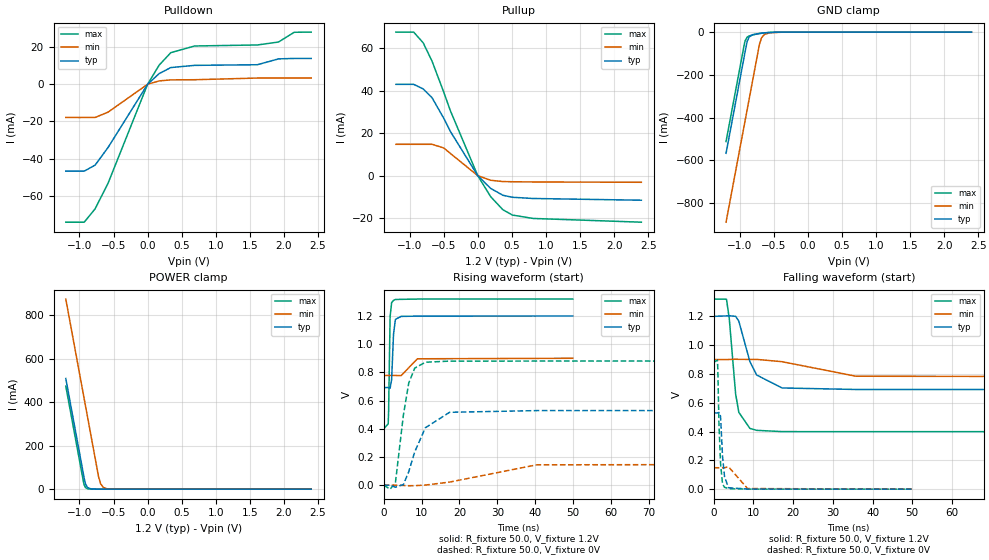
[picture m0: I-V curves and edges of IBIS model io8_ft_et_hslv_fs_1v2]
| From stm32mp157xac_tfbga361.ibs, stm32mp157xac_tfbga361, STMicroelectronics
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[Model]   io8_ft_et_hslv_fs_1v2
Model_type I/O
Polarity   Non-Inverting
Enable   Active-Low
| CAP_THRESHOLD on pad IOFT is "UDTCAPC" :
| Rising=20.00f vddiom   Falling=80.00f vddiom
| C_comp min and max val. don't necessarily correlate with the min and max pvt
| but are the smallest and greatest pad capacitance found.
| var   typ   min   max
C_comp   3.10945pF  3.08840pF  3.12935pF
|C_comp_pullup   1.82175pF  1.58940pF  1.75355pF
|C_comp_pulldown   1.28770pF  1.49900pF  1.37580pF
Vinl = 360.0mV
Vinh = 792.0mV
Vmeas = 600.0mV   | Reference voltage for timing measurements
Cref  = 50.0pF   | Timing specification test load capacitance value
Rref  = 100.0MOhm   | Timing specification test load resistance value
Vref  = 0V   | Timing specification test load voltage
[Model Spec]
| TIME_THRESHOLD on pin ZIV11 is "CMOS" :
| Rising=40.00f vdd   Falling=60.00f vdd
Vinl 463.60000mV 362.60000mV 506.60000mV
Vinh 741.40000mV 545.40000mV 817.40000mV
| variable   typ   min   max
[Temperature Range] 25.0 140.0 -40.0
| variable   typ   min   max
[Voltage Range] 1.2V 900.0mV 1.32V
| variable   typ   min   max
[POWER Clamp Reference] 1.2V 900.0mV 1.32V
| variable   typ   min   max
[GND Clamp Reference] 0V 0V 0V
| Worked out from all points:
|   slope of the pulldown table from 0 to 0.18 V, typ, clamps not added: 30 ohm
|   slope of the pullup table from 0 to 0.18 V, typ, clamps not added: 31.1 ohm
|   GND clamp passes 1 mA (typ) near -0.52 V on its own axis
|   POWER clamp passes 1 mA (typ) near -0.83 V on its own axis
|   rising waveform, R_fixture 50.0, V_fixture 1.2V: 20-80 % time 468ps typ, 1.3ns min, 301ps max; typ from 0.692 V to 1.2 V
|   falling waveform, R_fixture 50.0, V_fixture 1.2V: 20-80 % time 3.66ns typ, 9.09ns min, 1.85ns max; typ from 1.2 V to 0.692 V
|   rising waveform, R_fixture 50.0, V_fixture 0V: 20-80 % time 4.66ns typ, 10.8ns min, 2.55ns max; typ from 0 V to 0.529 V
|   falling waveform, R_fixture 50.0, V_fixture 0V: 20-80 % time 758ps typ, 1.48ns min, 607ps max; typ from 0.529 V to 0 V
[POWER Clamp]
-1.2V     508.8mA    874.1mA    473.5mA
-940mV    66.83mA    432.1mA    31.5mA
-930mV    49.83mA    415.1mA    19.15mA
-910mV    22.88mA    381.1mA    7.077mA
-880mV    7.117mA    330.1mA    1.59mA
-830mV    1.017mA    245.1mA    132uA
-720mV    14.05uA    58.12mA    554nA
-690mV    4.373uA    25.03mA    124.8nA
-650mV    922.5nA    8.136mA    17.23nA
-600mV    132.6nA    1.998mA    1.565nA
-490mV    2.857nA    90.92uA    111.8pA
2.4V      0A         0A         0A
[GND Clamp]
-1.2V     -567.2mA   -889.7mA   -512.2mA
-930mV    -108.2mA   -430.7mA   -53.23mA
-920mV    -91.21mA   -413.7mA   -40.49mA
-890mV    -43.51mA   -362.7mA   -23.59mA
-860mV    -22.57mA   -311.7mA   -17.89mA
-810mV    -12.11mA   -226.7mA   -13.23mA
-710mV    -6.053mA   -57.05mA   -7.064mA
-680mV    -4.908mA   -27.37mA   -5.632mA
-640mV    -3.605mA   -11.51mA   -3.985mA
-560mV    -1.665mA   -3.218mA   -1.61mA
-360mV    -34.72uA   -209.4uA   -9.248uA
2.4V      3.415nA    1.206uA    162.7pA
| variable   typ   min   max
[Pullup Reference] 1.2V 900.0mV 1.32V
| variable   typ   min   max
[Pulldown Reference] 0V 0V 0V
[Pullup]
-1.2V     43.05mA    14.77mA    67.68mA
-940mV    43.05mA    14.77mA    67.68mA
-800mV    40.87mA    14.77mA    62.62mA
-670mV    36.74mA    14.77mA    53.95mA
-500mV    27.13mA    13.06mA    39.48mA
-400mV    20.77mA    10.43mA    30.5mA
0V        5.9pA      1.254nA    2.839pA
190mV     -6.046mA   -2.202mA   -9.95mA
370mV     -9.277mA   -2.804mA   -16.11mA
510mV     -10.21mA   -2.889mA   -18.61mA
810mV     -10.78mA   -2.991mA   -20.19mA
2.4V      -11.6mA    -3.14mA    -21.96mA
[Pulldown]
-1.2V     -46.7mA    -17.86mA   -74.13mA
-930mV    -46.7mA    -17.86mA   -74.13mA
-770mV    -43.45mA   -17.86mA   -66.94mA
-580mV    -33.98mA   -14.99mA   -53.18mA
0V        0A         -6pA       0A
170mV     5.742mA    1.791mA    10.3mA
340mV     8.972mA    2.348mA    16.97mA
690mV     10.15mA    2.431mA    20.56mA
1.61V     10.49mA    3.333mA    21.11mA
1.92V     13.63mA    3.333mA    22.69mA
2.15V     13.87mA    3.333mA    27.93mA
2.4V      13.87mA    3.333mA    28.03mA
[Ramp]
dV/dt_r 317.40516mV/4.65968ns 89.22448mV/10.83757ns 528.12582mV/2.54544ns
dV/dt_f 304.67127mV/3.65947ns 73.1909mV/9.0937ns 552.41131mV/1.85188ns
R_load = 50.0
| Removed startup time: 0s 0s 0s  .
| Removed end time: 49.9ns.
[Rising Waveform]
R_fixture   = 50.0
V_fixture   = 1.2V
V_fixture_min = 900.0mV
V_fixture_max = 1.32V
0s        692.2mV    778mV      399.3mV
1.2ns     692.4mV    778.1mV    434.3mV
1.3ns     692.7mV    778.1mV    514.4mV
1.7ns     686.8mV    778.1mV    1.195V
2.1ns     748.5mV    778.1mV    1.294V
2.6ns     1.07V      778.1mV    1.311V
3.1ns     1.176V     778.1mV    1.317V
4.6ns     1.197V     776.6mV    1.318V
8.9ns     1.199V     896.3mV    1.32V
49.9ns    1.2V       900mV      1.32V
| Removed startup time: 0s 0s 0s  .
| Removed end time: 199.9ns.
[Falling Waveform]
R_fixture   = 50.0
V_fixture   = 1.2V
V_fixture_min = 900.0mV
V_fixture_max = 1.32V
0s        1.2V       900mV      1.32V
3.2ns     1.203V     899.7mV    1.319V
3.9ns     1.204V     900.6mV    1.185V
5.5ns     1.2V       902.2mV    662mV
6.3ns     1.167V     901.4mV    533.6mV
9.1ns     885.6mV    901mV      421.9mV
10.8ns    792.5mV    901.1mV    408.5mV
17.2ns    702.7mV    885.1mV    399.7mV
35.8ns    692.2mV    784.2mV    399.3mV
199.9ns   692.2mV    778mV      399.3mV
| Removed startup time: 0s 0s 0s  .
| Removed end time: 199.9ns.
[Rising Waveform]
R_fixture   = 50.0
V_fixture   = 0V
V_fixture_min = 0V
V_fixture_max = 0V
0s        -113.9nV   228.8nV    -3.894uV
1.7ns     -691.8uV   131.1nV    -28.53mV
3.1ns     -14.31mV   -34.12uV   15.69mV
5.2ns     4.035mV    -2.191mV   496.6mV
6.6ns     94.03mV    -4.132mV   722.8mV
8.2ns     236.4mV    -3.48mV    830.1mV
11ns      407.1mV    565.1uV    871.9mV
17.4ns    516.7mV    21.78mV    879.8mV
40.4ns    528.8mV    144.3mV    880.2mV
199.9ns   529mV      148.7mV    880.2mV
| Removed startup time: 0s 0s 0s  .
| Removed end time: 49.9ns.
[Falling Waveform]
R_fixture   = 50.0
V_fixture   = 0V
V_fixture_min = 0V
V_fixture_max = 0V
0s        529mV      148.8mV    880.2mV
900ps     529.2mV    148.8mV    896.6mV
1ns       529.1mV    148.8mV    850.2mV
1.3ns     532.7mV    148.8mV    459.4mV
1.7ns     508.3mV    148.8mV    181.2mV
2.2ns     229.3mV    148.8mV    36.68mV
2.7ns     88.29mV    148.6mV    13.35mV
3.7ns     9.973mV    156mV      3.432mV
8.5ns     1.024mV    4.302mV    216.5uV
49.9ns    -203.7nV   5.137uV    729.3nV
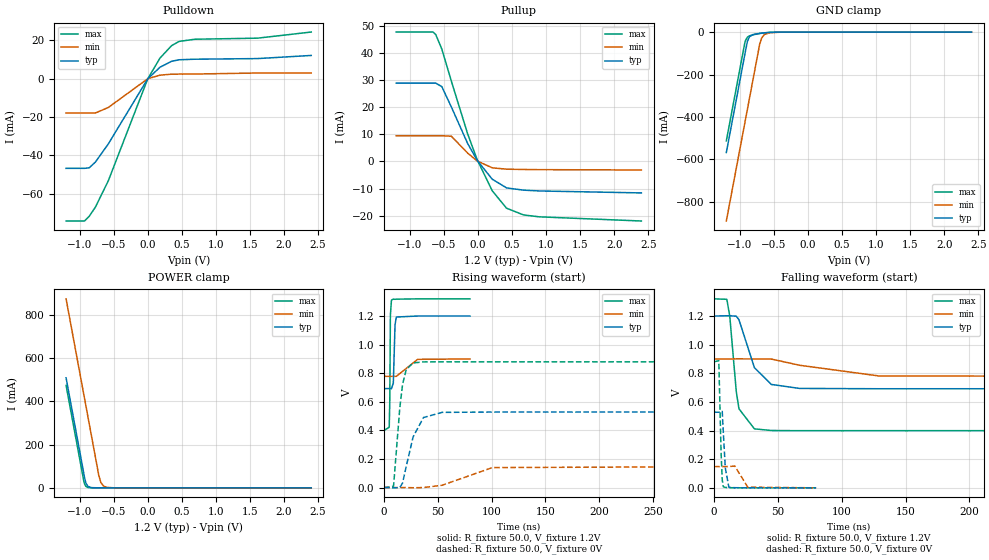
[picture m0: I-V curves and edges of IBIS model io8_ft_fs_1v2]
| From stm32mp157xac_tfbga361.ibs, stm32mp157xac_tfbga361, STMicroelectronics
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[Model]   io8_ft_fs_1v2
Model_type I/O
Polarity   Non-Inverting
Enable   Active-Low
| CAP_THRESHOLD on pad IOFT is "UDTCAPC" :
| Rising=20.00f vddiom   Falling=80.00f vddiom
| C_comp min and max val. don't necessarily correlate with the min and max pvt
| but are the smallest and greatest pad capacitance found.
| var   typ   min   max
C_comp   3.10955pF  3.08205pF  3.12755pF
|C_comp_pullup   1.83575pF  1.59880pF  1.76540pF
|C_comp_pulldown   1.27380pF  1.48325pF  1.36215pF
Vinl = 360.0mV
Vinh = 792.0mV
Vmeas = 600.0mV   | Reference voltage for timing measurements
Cref  = 50.0pF   | Timing specification test load capacitance value
Rref  = 100.0MOhm   | Timing specification test load resistance value
Vref  = 0V   | Timing specification test load voltage
[Model Spec]
| TIME_THRESHOLD on pin ZIV11 is "CMOS" :
| Rising=40.00f vdd   Falling=60.00f vdd
Vinl 463.60000mV 362.60000mV 506.60000mV
Vinh 741.40000mV 545.40000mV 817.40000mV
| variable   typ   min   max
[Temperature Range] 25.0 140.0 -40.0
| variable   typ   min   max
[Voltage Range] 1.2V 900.0mV 1.32V
| variable   typ   min   max
[POWER Clamp Reference] 1.2V 900.0mV 1.32V
| variable   typ   min   max
[GND Clamp Reference] 0V 0V 0V
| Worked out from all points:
|   slope of the pulldown table from 0 to 0.18 V, typ, clamps not added: 30 ohm
|   slope of the pullup table from 0 to 0.18 V, typ, clamps not added: 31.1 ohm
|   GND clamp passes 1 mA (typ) near -0.52 V on its own axis
|   POWER clamp passes 1 mA (typ) near -0.83 V on its own axis
|   rising waveform, R_fixture 50.0, V_fixture 1.2V: 20-80 % time 985ps typ, 2.96ns min, 509ps max; typ from 0.692 V to 1.2 V
|   falling waveform, R_fixture 50.0, V_fixture 1.2V: 20-80 % time 11.9ns typ, 31.2ns min, 5.82ns max; typ from 1.2 V to 0.692 V
|   rising waveform, R_fixture 50.0, V_fixture 0V: 20-80 % time 10.9ns typ, 26.5ns min, 6ns max; typ from 0 V to 0.528 V
|   falling waveform, R_fixture 50.0, V_fixture 0V: 20-80 % time 2.15ns typ, 4.87ns min, 1.52ns max; typ from 0.528 V to 0 V
[POWER Clamp]
-1.2V     508.8mA    874.1mA    473.5mA
-940mV    66.83mA    432.1mA    31.5mA
-930mV    49.83mA    415.1mA    19.15mA
-910mV    22.88mA    381.1mA    7.077mA
-880mV    7.117mA    330.1mA    1.59mA
-830mV    1.017mA    245.1mA    132uA
-720mV    14.05uA    58.12mA    554nA
-690mV    4.373uA    25.03mA    124.7nA
-650mV    922.4nA    8.136mA    17.22nA
-600mV    132.5nA    1.998mA    1.555nA
-490mV    2.763nA    90.9uA     103.5pA
2.4V      0A         0A         0A
[GND Clamp]
-1.2V     -567.2mA   -889.7mA   -512.2mA
-930mV    -108.2mA   -430.7mA   -53.23mA
-920mV    -91.21mA   -413.7mA   -40.49mA
-890mV    -43.51mA   -362.7mA   -23.59mA
-860mV    -22.57mA   -311.7mA   -17.89mA
-810mV    -12.11mA   -226.7mA   -13.23mA
-710mV    -6.053mA   -57.05mA   -7.064mA
-680mV    -4.908mA   -27.37mA   -5.632mA
-640mV    -3.605mA   -11.51mA   -3.985mA
-560mV    -1.665mA   -3.218mA   -1.61mA
-360mV    -34.72uA   -209.4uA   -9.248uA
2.4V      3.381nA    1.198uA    162.5pA
| variable   typ   min   max
[Pullup Reference] 1.2V 900.0mV 1.32V
| variable   typ   min   max
[Pulldown Reference] 0V 0V 0V
[Pullup]
-1.2V     28.87mA    9.491mA    47.69mA
-660mV    28.87mA    9.491mA    47.69mA
-620mV    28.87mA    9.491mA    46.79mA
-530mV    27.58mA    9.491mA    41.4mA
-390mV    20.06mA    9.307mA    29.58mA
-150mV    6.588mA    3.07mA     10.09mA
-10mV     390.4uA    167.5uA    614.6uA
210mV     -6.52mA    -2.327mA   -10.79mA
420mV     -9.73mA    -2.836mA   -17.21mA
670mV     -10.56mA   -2.945mA   -19.69mA
900mV     -10.86mA   -3.008mA   -20.39mA
2.4V      -11.58mA   -3.134mA   -21.93mA
[Pulldown]
-1.2V     -46.7mA    -17.86mA   -74.13mA
-930mV    -46.7mA    -17.86mA   -74.13mA
-860mV    -46.38mA   -17.86mA   -71.67mA
-770mV    -43.45mA   -17.86mA   -66.94mA
-580mV    -33.98mA   -14.99mA   -53.18mA
0V        0A         0A         0A
180mV     6.001mA    1.854mA    10.79mA
350mV     9.086mA    2.357mA    17.24mA
460mV     9.857mA    2.4mA      19.42mA
690mV     10.15mA    2.431mA    20.56mA
1.61V     10.48mA    2.965mA    21.11mA
2.4V      12.11mA    2.965mA    24.31mA
[Ramp]
dV/dt_r 316.98806mV/10.92883ns 89.06952mV/26.53339ns 527.83461mV/5.99712ns
dV/dt_f 304.65485mV/11.86665ns 73.18637mV/31.18645ns 552.41147mV/5.81808ns
R_load = 50.0
| Removed startup time: 0s 0s 0s  .
| Removed end time: 79.9ns.
[Rising Waveform]
R_fixture   = 50.0
V_fixture   = 1.2V
V_fixture_min = 900.0mV
V_fixture_max = 1.32V
0s        692.2mV    778mV      399.3mV
4.9ns     692.2mV    778mV      421.6mV
5.4ns     692.2mV    778mV      597.4mV
6ns       692.3mV    778mV      1.21V
7ns       691.6mV    778mV      1.312V
8.7ns     730.7mV    778mV      1.318V
10.3ns    1.14V      778mV      1.317V
11.5ns    1.193V     778mV      1.318V
31.3ns    1.2V       896.9mV    1.32V
79.9ns    1.2V       899.9mV    1.32V
| Removed startup time: 0s 0s 0s  .
| Removed end time: 399.9ns.
[Falling Waveform]
R_fixture   = 50.0
V_fixture   = 1.2V
V_fixture_min = 900.0mV
V_fixture_max = 1.32V
0s        1.2V       900mV      1.32V
10ns      1.202V     900mV      1.317V
12.3ns    1.202V     900mV      1.198V
17.4ns    1.199V     900.8mV    671.9mV
19.5ns    1.174V     900.8mV    551.9mV
31.6ns    839.2mV    900.6mV    411.9mV
44.9ns    722.1mV    899.5mV    400.6mV
67ns      694.4mV    856.3mV    399.3mV
129.1ns   692.2mV    781.5mV    399.3mV
399.9ns   692.2mV    778mV      399.3mV
| Removed startup time: 0s 0s 0s  .
| Removed end time: 399.9ns.
[Rising Waveform]
R_fixture   = 50.0
V_fixture   = 0V
V_fixture_min = 0V
V_fixture_max = 0V
0s        51.09nV    1.017uV    136.6nV
8.9ns     -2.083mV   1.096uV    9.2mV
14.7ns    -58.18uV   1.134uV    555.3mV
17.3ns    31.54mV    -474.8nV   722.2mV
20.7ns    147.9mV    39.74uV    826.1mV
27.1ns    354.9mV    -1.394mV   871.8mV
36.7ns    489.8mV    -12.02uV   879mV
54ns      525.9mV    16.01mV    879.7mV
100.7ns   528.2mV    139.7mV    879.7mV
399.9ns   528.3mV    148.5mV    879.7mV
| Removed startup time: 0s 0s 0s  .
| Removed end time: 79.9ns.
[Falling Waveform]
R_fixture   = 50.0
V_fixture   = 0V
V_fixture_min = 0V
V_fixture_max = 0V
0s        528.3mV    148.5mV    879.7mV
3.7ns     528.3mV    148.5mV    889mV
5.5ns     529mV      148.5mV    244mV
6.4ns     534.3mV    148.5mV    57.18mV
7.2ns     394.6mV    148.5mV    7.815mV
8.8ns     139.1mV    148.5mV    2.844mV
11.6ns    3.698mV    148.5mV    1.505mV
16.2ns    1.007mV    152.5mV    493.8uV
26.4ns    383uV      4.723mV    75.22uV
79.9ns    728.4nV    93.74uV    -1.738uV
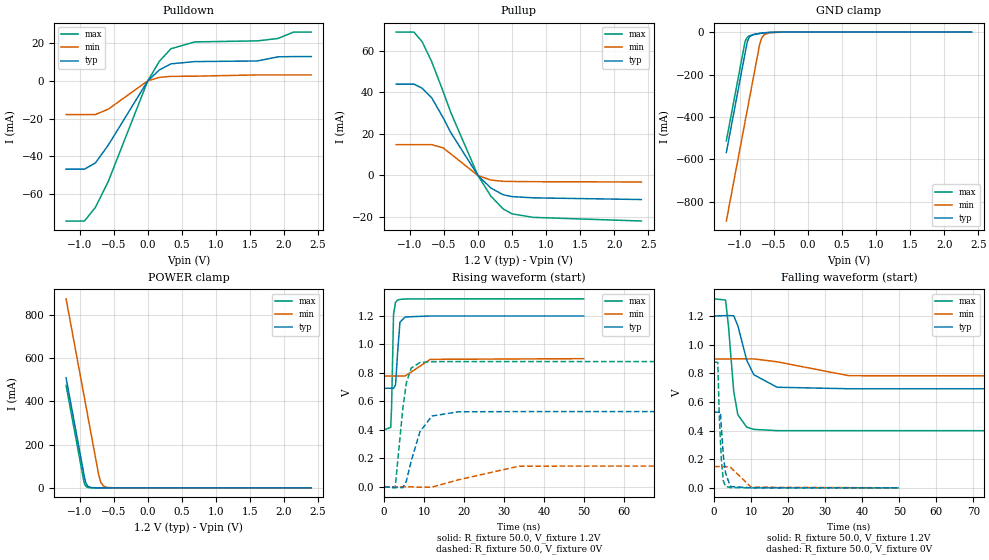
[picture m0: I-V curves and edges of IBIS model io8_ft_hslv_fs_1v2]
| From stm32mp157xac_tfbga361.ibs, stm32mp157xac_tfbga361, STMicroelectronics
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[Model]   io8_ft_hslv_fs_1v2
Model_type I/O
Polarity   Non-Inverting
Enable   Active-Low
| CAP_THRESHOLD on pad IOFT is "UDTCAPC" :
| Rising=20.00f vddiom   Falling=80.00f vddiom
| C_comp min and max val. don't necessarily correlate with the min and max pvt
| but are the smallest and greatest pad capacitance found.
| var   typ   min   max
C_comp   3.08865pF  3.06550pF  3.10825pF
|C_comp_pullup   1.81640pF  1.58310pF  1.74795pF
|C_comp_pulldown   1.27225pF  1.48240pF  1.36030pF
Vinl = 360.0mV
Vinh = 792.0mV
Vmeas = 600.0mV   | Reference voltage for timing measurements
Cref  = 50.0pF   | Timing specification test load capacitance value
Rref  = 100.0MOhm   | Timing specification test load resistance value
Vref  = 0V   | Timing specification test load voltage
[Model Spec]
| TIME_THRESHOLD on pin ZIV11 is "CMOS" :
| Rising=40.00f vdd   Falling=60.00f vdd
Vinl 463.60000mV 362.60000mV 506.60000mV
Vinh 741.40000mV 545.40000mV 817.40000mV
| variable   typ   min   max
[Temperature Range] 25.0 140.0 -40.0
| variable   typ   min   max
[Voltage Range] 1.2V 900.0mV 1.32V
| variable   typ   min   max
[POWER Clamp Reference] 1.2V 900.0mV 1.32V
| variable   typ   min   max
[GND Clamp Reference] 0V 0V 0V
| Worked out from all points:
|   slope of the pulldown table from 0 to 0.18 V, typ, clamps not added: 30 ohm
|   slope of the pullup table from 0 to 0.18 V, typ, clamps not added: 31.1 ohm
|   GND clamp passes 1 mA (typ) near -0.52 V on its own axis
|   POWER clamp passes 1 mA (typ) near -0.83 V on its own axis
|   rising waveform, R_fixture 50.0, V_fixture 1.2V: 20-80 % time 620ps typ, 1.67ns min, 371ps max; typ from 0.692 V to 1.2 V
|   falling waveform, R_fixture 50.0, V_fixture 1.2V: 20-80 % time 3.79ns typ, 9.34ns min, 1.91ns max; typ from 1.2 V to 0.692 V
|   rising waveform, R_fixture 50.0, V_fixture 0V: 20-80 % time 3.38ns typ, 7.7ns min, 1.88ns max; typ from 0 V to 0.528 V
|   falling waveform, R_fixture 50.0, V_fixture 0V: 20-80 % time 1.12ns typ, 2.38ns min, 842ps max; typ from 0.528 V to 0 V
[POWER Clamp]
-1.2V     508.8mA    874.1mA    473.5mA
-940mV    66.83mA    432.1mA    31.5mA
-930mV    49.83mA    415.1mA    19.15mA
-910mV    22.88mA    381.1mA    7.077mA
-880mV    7.117mA    330.1mA    1.59mA
-830mV    1.017mA    245.1mA    132uA
-720mV    14.05uA    58.12mA    554nA
-690mV    4.373uA    25.03mA    124.7nA
-650mV    922.4nA    8.136mA    17.22nA
-600mV    132.5nA    1.998mA    1.555nA
-490mV    2.736nA    90.9uA     103pA
2.4V      0A         0A         0A
[GND Clamp]
-1.2V     -567.2mA   -889.7mA   -512.2mA
-930mV    -108.2mA   -430.7mA   -53.23mA
-920mV    -91.21mA   -413.7mA   -40.49mA
-890mV    -43.51mA   -362.7mA   -23.59mA
-860mV    -22.57mA   -311.7mA   -17.89mA
-810mV    -12.11mA   -226.7mA   -13.23mA
-710mV    -6.053mA   -57.05mA   -7.064mA
-680mV    -4.908mA   -27.37mA   -5.632mA
-640mV    -3.605mA   -11.51mA   -3.985mA
-560mV    -1.665mA   -3.218mA   -1.61mA
-360mV    -34.72uA   -209.4uA   -9.248uA
2.4V      3.381nA    1.198uA    162.5pA
| variable   typ   min   max
[Pullup Reference] 1.2V 900.0mV 1.32V
| variable   typ   min   max
[Pulldown Reference] 0V 0V 0V
[Pullup]
-1.2V     44.02mA    14.86mA    69.12mA
-940mV    44.02mA    14.86mA    69.12mA
-820mV    42.05mA    14.86mA    64.49mA
-680mV    37.49mA    14.86mA    54.96mA
-510mV    27.78mA    13.29mA    40.38mA
-400mV    20.76mA    10.44mA    30.48mA
0V        5.9pA      1.254nA    2.839pA
190mV     -6.04mA    -2.199mA   -9.942mA
370mV     -9.266mA   -2.799mA   -16.1mA
500mV     -10.16mA   -2.878mA   -18.47mA
810mV     -10.76mA   -2.985mA   -20.17mA
2.4V      -11.58mA   -3.134mA   -21.93mA
[Pulldown]
-1.2V     -46.7mA    -17.86mA   -74.13mA
-930mV    -46.7mA    -17.86mA   -74.13mA
-770mV    -43.45mA   -17.86mA   -66.94mA
-580mV    -33.98mA   -14.99mA   -53.18mA
0V        0A         -3pA       0A
170mV     5.742mA    1.791mA    10.3mA
340mV     8.972mA    2.348mA    16.97mA
690mV     10.15mA    2.431mA    20.56mA
1.61V     10.49mA    3.108mA    21.11mA
1.91V     12.66mA    3.108mA    22.36mA
2.14V     12.8mA     3.108mA    25.73mA
2.4V      12.8mA     3.108mA    25.78mA
[Ramp]
dV/dt_r 316.99369mV/3.37853ns 89.07484mV/7.69904ns 527.83664mV/1.87906ns
dV/dt_f 304.66875mV/3.7948ns 73.16553mV/9.3317ns 552.41104mV/1.90745ns
R_load = 50.0
| Removed startup time: 0s 0s 0s  .
| Removed end time: 49.9ns.
[Rising Waveform]
R_fixture   = 50.0
V_fixture   = 1.2V
V_fixture_min = 900.0mV
V_fixture_max = 1.32V
0s        692.2mV    778mV      399.3mV
1.7ns     692.5mV    778.1mV    418mV
1.9ns     692.5mV    778.1mV    552.4mV
2.4ns     690.8mV    778.1mV    1.213V
2.9ns     716.9mV    778.1mV    1.296V
3.4ns     936.8mV    778.1mV    1.311V
4ns       1.156V     778.1mV    1.316V
5.3ns     1.193V     778.1mV    1.319V
11.6ns    1.2V       895.3mV    1.32V
49.9ns    1.2V       900mV      1.32V
| Removed startup time: 0s 0s 0s  .
| Removed end time: 199.9ns.
[Falling Waveform]
R_fixture   = 50.0
V_fixture   = 1.2V
V_fixture_min = 900.0mV
V_fixture_max = 1.32V
0s        1.2V       900mV      1.32V
3.1ns     1.203V     900mV      1.312V
3.9ns     1.203V     899.8mV    1.125V
5.3ns     1.202V     902mV      674.8mV
6.4ns     1.134V     901.2mV    511.6mV
8.8ns     892.9mV    900.8mV    424.1mV
10.7ns    790.5mV    900.8mV    408.3mV
17ns      702.7mV    880.4mV    399.7mV
36.4ns    692.2mV    783.3mV    399.3mV
199.9ns   692.2mV    778.1mV    399.3mV
| Removed startup time: 0s 0s 0s  .
| Removed end time: 199.9ns.
[Rising Waveform]
R_fixture   = 50.0
V_fixture   = 0V
V_fixture_min = 0V
V_fixture_max = 0V
0s        -2.959nV   714nV      -2.512uV
2.8ns     -4.669mV   -693.2nV   -7.223mV
4.7ns     -5.96mV    -772.3nV   545.7mV
5.6ns     40.48mV    20.77uV    729.4mV
6.8ns     179.7mV    -174.4uV   833.6mV
9ns       387.6mV    -2.734mV   873.3mV
12ns      497.2mV    -2.041mV   879mV
18.6ns    527mV      49.27mV    879.6mV
33.7ns    528.2mV    145.1mV    879.7mV
199.9ns   528.3mV    148.5mV    879.7mV
| Removed startup time: 0s 0s 0s  .
| Removed end time: 49.9ns.
[Falling Waveform]
R_fixture   = 50.0
V_fixture   = 0V
V_fixture_min = 0V
V_fixture_max = 0V
0s        528.3mV    148.5mV    879.7mV
1ns       528.4mV    148.5mV    876mV
1.4ns     529.2mV    148.5mV    513.2mV
1.7ns     529.5mV    148.5mV    338mV
2ns       408.5mV    148.5mV    186.8mV
2.5ns     226.1mV    148.5mV    48.8mV
3.1ns     103.2mV    148.4mV    9.756mV
4.4ns     9.273mV    144.4mV    2.198mV
10ns      553.3uV    4.627mV    101.8uV
49.9ns    40.25nV    4.241uV    87.64nV
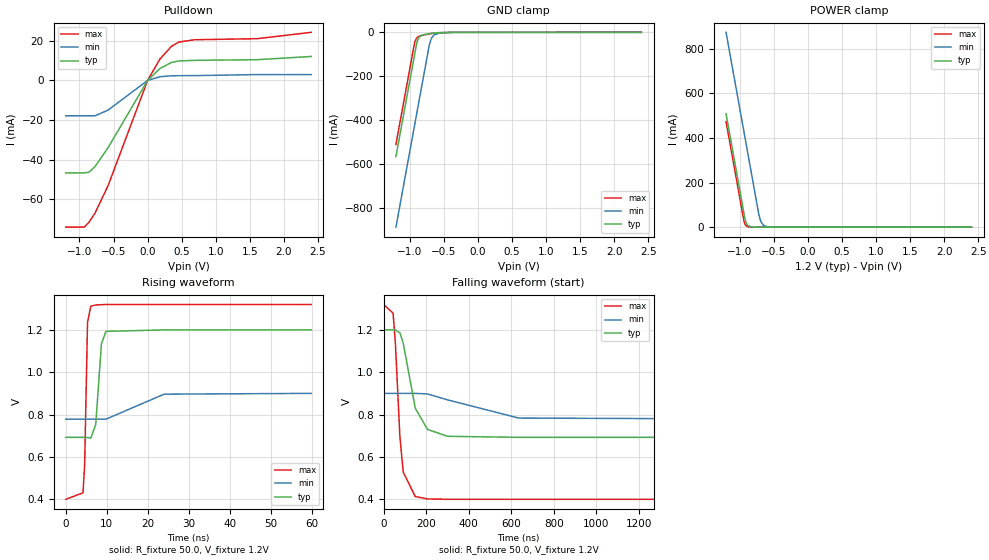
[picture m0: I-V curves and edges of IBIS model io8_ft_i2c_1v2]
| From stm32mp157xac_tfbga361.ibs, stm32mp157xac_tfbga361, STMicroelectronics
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[Model]   io8_ft_i2c_1v2
Model_type I/O_open_drain
Polarity   Non-Inverting
Enable   Active-Low
| CAP_THRESHOLD on pad IOFT is "UDTCAPC" :
| Rising=20.00f vddiom   Falling=80.00f vddiom
| C_comp min and max val. don't necessarily correlate with the min and max pvt
| but are the smallest and greatest pad capacitance found.
| var   typ   min   max
C_comp   3.10100pF  3.07370pF  3.11875pF
|C_comp_pulldown   3.10100pF  3.07370pF  3.11875pF
Vinl = 360.0mV
Vinh = 792.0mV
Vmeas = 600.0mV   | Reference voltage for timing measurements
Cref  = 50.0pF   | Timing specification test load capacitance value
Rref  = 100.0MOhm   | Timing specification test load resistance value
Vref  = 600.0mV   | Timing specification test load voltage
[Model Spec]
| TIME_THRESHOLD on pin ZIV11 is "CMOS" :
| Rising=40.00f vdd   Falling=60.00f vdd
Vinl 463.60000mV 362.60000mV 506.60000mV
Vinh 742.40000mV 546.40000mV 818.40000mV
| variable   typ   min   max
[Temperature Range] 25.0 140.0 -40.0
| variable   typ   min   max
[Voltage Range] 1.2V 900.0mV 1.32V
| variable   typ   min   max
[POWER Clamp Reference] 1.2V 900.0mV 1.32V
| variable   typ   min   max
[GND Clamp Reference] 0V 0V 0V
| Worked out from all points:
|   slope of the pulldown table from 0 to 0.18 V, typ, clamps not added: 30 ohm
|   GND clamp passes 1 mA (typ) near -0.52 V on its own axis
|   POWER clamp passes 1 mA (typ) near -0.83 V on its own axis
|   rising waveform, R_fixture 50.0, V_fixture 1.2V: 20-80 % time 986ps typ, 3ns min, 509ps max; typ from 0.692 V to 1.2 V
|   falling waveform, R_fixture 50.0, V_fixture 1.2V: 20-80 % time 62.8ns typ, 194ns min, 29.8ns max; typ from 1.2 V to 0.692 V
[POWER Clamp]
-1.2V     508.8mA    874.1mA    473.5mA
-940mV    66.83mA    432.1mA    31.5mA
-930mV    49.83mA    415.1mA    19.15mA
-910mV    22.88mA    381.1mA    7.077mA
-880mV    7.117mA    330.1mA    1.59mA
-830mV    1.017mA    245.1mA    132uA
-720mV    14.05uA    58.12mA    554nA
-690mV    4.373uA    25.03mA    124.7nA
-650mV    922.4nA    8.136mA    17.22nA
-600mV    132.5nA    1.998mA    1.555nA
-490mV    2.763nA    90.9uA     103.5pA
2.4V      0A         0A         0A
[GND Clamp]
-1.2V     -567.2mA   -889.7mA   -512.2mA
-930mV    -108.2mA   -430.7mA   -53.23mA
-920mV    -91.21mA   -413.7mA   -40.49mA
-890mV    -43.51mA   -362.7mA   -23.59mA
-860mV    -22.57mA   -311.7mA   -17.89mA
-810mV    -12.11mA   -226.7mA   -13.23mA
-710mV    -6.053mA   -57.05mA   -7.064mA
-680mV    -4.908mA   -27.37mA   -5.632mA
-640mV    -3.605mA   -11.51mA   -3.985mA
-560mV    -1.665mA   -3.218mA   -1.61mA
-360mV    -34.72uA   -209.4uA   -9.248uA
2.4V      3.381nA    1.198uA    162.5pA
| variable   typ   min   max
[Pullup Reference] 1.2V 900.0mV 1.32V
| variable   typ   min   max
[Pulldown Reference] 0V 0V 0V
[Pulldown]
-1.2V     -46.7mA    -17.86mA   -74.13mA
-930mV    -46.7mA    -17.86mA   -74.13mA
-860mV    -46.38mA   -17.86mA   -71.67mA
-770mV    -43.45mA   -17.86mA   -66.94mA
-580mV    -33.98mA   -14.99mA   -53.18mA
0V        0A         0A         0A
180mV     6.001mA    1.854mA    10.79mA
350mV     9.086mA    2.357mA    17.24mA
460mV     9.857mA    2.399mA    19.42mA
690mV     10.15mA    2.431mA    20.56mA
1.61V     10.48mA    2.965mA    21.11mA
2.4V      12.11mA    2.965mA    24.31mA
[Ramp]
dV/dt_r 304.65256mV/982.57714ps 73.15215mV/3.00436ns 552.40179mV/502.08835ps
dV/dt_f 304.65857mV/62.78227ns 73.18216mV/174.50845ns 552.41397mV/29.81965ns
R_load = 50.0
| Removed startup time: 0s 0s 0s  .
| Removed end time: 59.9ns.
[Rising Waveform]
R_fixture   = 50.0
V_fixture   = 1.2V
V_fixture_min = 900.0mV
V_fixture_max = 1.32V
0s        692.2mV    778mV      399.3mV
4.2ns     692.3mV    778mV      430.2mV
4.6ns     692.2mV    778mV      561.9mV
5.3ns     691.4mV    778mV      1.234V
6.1ns     688.2mV    778mV      1.312V
7.3ns     753.3mV    778mV      1.318V
8.7ns     1.134V     778mV      1.319V
9.8ns     1.193V     778.1mV    1.32V
24ns      1.2V       896.3mV    1.32V
59.9ns    1.2V       900mV      1.32V
| Removed startup time: 0s 0s 0s  .
| Removed end time: 1.9999us.
[Falling Waveform]
R_fixture   = 50.0
V_fixture   = 1.2V
V_fixture_min = 900.0mV
V_fixture_max = 1.32V
0s        1.2V       900mV      1.32V
44.4ns    1.2V       900mV      1.279V
55.1ns    1.2V       900mV      1.139V
76.3ns    1.186V     900mV      696.9mV
92.1ns    1.137V     900mV      527mV
148.8ns   829.8mV    899.9mV    412.5mV
206ns     729.9mV    897.4mV    401.1mV
299.7ns   697.2mV    869.5mV    399.4mV
634.7ns   692.2mV    783.4mV    399.3mV
2us       692.2mV    778mV      399.3mV
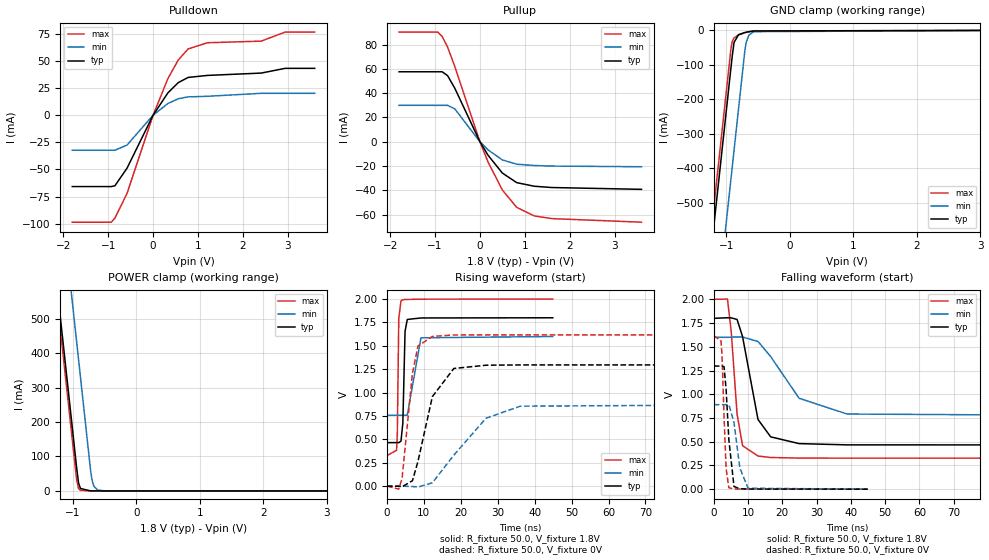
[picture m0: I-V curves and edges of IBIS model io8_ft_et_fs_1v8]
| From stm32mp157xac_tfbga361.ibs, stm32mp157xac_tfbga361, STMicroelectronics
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[Model]   io8_ft_et_fs_1v8
Model_type I/O
Polarity   Non-Inverting
Enable   Active-Low
| CAP_THRESHOLD on pad IOFT is "UDTCAPC" :
| Rising=20.00f vddiom   Falling=80.00f vddiom
| C_comp min and max val. don't necessarily correlate with the min and max pvt
| but are the smallest and greatest pad capacitance found.
| var   typ   min   max
C_comp   3.43098pF  3.42356pF  3.49925pF
|C_comp_pullup   1.96705pF  2.05925pF  1.91840pF
|C_comp_pulldown   1.46393pF  1.36431pF  1.58085pF
Vinl = 640.0mV
Vinh = 1.2V
Vmeas = 900.0mV   | Reference voltage for timing measurements
Cref  = 50.0pF   | Timing specification test load capacitance value
Rref  = 100.0MOhm   | Timing specification test load resistance value
Vref  = 0V   | Timing specification test load voltage
[Model Spec]
| TIME_THRESHOLD on pin ZIV11 is "CMOS" :
| Rising=40.00f vdd   Falling=60.00f vdd
Vinl 738.60000mV 665.60000mV 824.60000mV
Vinh 1.04640V 924.40000mV 1.13940V
| variable   typ   min   max
[Temperature Range] 25.0 140.0 -40.0
| variable   typ   min   max
[Voltage Range] 1.8V 1.6V 2.0V
| variable   typ   min   max
[POWER Clamp Reference] 1.8V 1.6V 2.0V
| variable   typ   min   max
[GND Clamp Reference] 0V 0V 0V
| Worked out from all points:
|   slope of the pulldown table from 0 to 0.27 V, typ, clamps not added: 16 ohm
|   slope of the pullup table from 0 to 0.27 V, typ, clamps not added: 17 ohm
|   GND clamp passes 1 mA (typ) near -0.52 V on its own axis
|   POWER clamp passes 1 mA (typ) near -0.83 V on its own axis
|   rising waveform, R_fixture 50.0, V_fixture 1.8V: 20-80 % time 434ps typ, 903ps min, 298ps max; typ from 0.466 V to 1.8 V
|   falling waveform, R_fixture 50.0, V_fixture 1.8V: 20-80 % time 4.06ns typ, 10.1ns min, 2.05ns max; typ from 1.8 V to 0.466 V
|   rising waveform, R_fixture 50.0, V_fixture 0V: 20-80 % time 4.57ns typ, 10.8ns min, 2.27ns max; typ from 0 V to 1.3 V
|   falling waveform, R_fixture 50.0, V_fixture 0V: 20-80 % time 1.33ns typ, 2.04ns min, 931ps max; typ from 1.3 V to 0 V
[POWER Clamp]
-1.8V     1.529A     1.894A     1.494A
-940mV    66.83mA    432.1mA    31.5mA
-910mV    22.88mA    381.1mA    7.077mA
-880mV    7.117mA    330.1mA    1.59mA
-720mV    14.05uA    58.12mA    554nA
-700mV    6.453uA    33.14mA    205nA
-670mV    2.008uA    14.27mA    46.29nA
-610mV    195.5nA    2.645mA    2.508nA
-500mV    3.962nA    120.4uA    139.7pA
3.6V      0A         0A         0A
[GND Clamp]
-1.8V     -1.588A    -1.91A     -1.533A
-1.26V    -670.3mA   -992.4mA   -614.9mA
-1.2V     -568.3mA   -890.4mA   -512.9mA
-930mV    -109.3mA   -431.4mA   -53.86mA
-910mV    -75.33mA   -397.4mA   -32.91mA
-880mV    -34.88mA   -346.4mA   -21.56mA
-810mV    -12.56mA   -227.4mA   -13.55mA
-710mV    -6.275mA   -57.63mA   -7.234mA
-690mV    -5.461mA   -35.21mA   -6.234mA
-650mV    -4.039mA   -14.43mA   -4.463mA
-570mV    -1.908mA   -3.832mA   -1.869mA
3.6V      5.084nA    1.599uA    245.6pA
| variable   typ   min   max
[Pullup Reference] 1.8V 1.6V 2.0V
| variable   typ   min   max
[Pulldown Reference] 0V 0V 0V
[Pullup]
-1.8V     57.58mA    29.93mA    90.27mA
-940mV    57.58mA    29.93mA    90.27mA
-840mV    57.58mA    29.93mA    86.65mA
-720mV    54.41mA    29.93mA    78mA
-560mV    44.11mA    27.09mA    61.99mA
0V        7.41pA     1.33nA     4.294pA
180mV     -11.09mA   -6.716mA   -16.63mA
500mV     -25.8mA    -15mA      -39.78mA
820mV     -33.72mA   -18.55mA   -54.08mA
1.21V     -36.68mA   -19.61mA   -61.13mA
1.6V      -37.75mA   -20.08mA   -63.35mA
3.6V      -39.24mA   -20.63mA   -66.3mA
[Pulldown]
-1.8V     -65.8mA    -32.31mA   -98.64mA
-930mV    -65.8mA    -32.31mA   -98.64mA
-850mV    -65.04mA   -32.31mA   -94.81mA
-580mV    -48.83mA   -27.49mA   -72.14mA
0V        0A         -3pA       0A
330mV     20.59mA    10.79mA    33.74mA
560mV     30.02mA    15.15mA    50.81mA
780mV     34.81mA    16.9mA     61.1mA
1.21V     36.69mA    17.44mA    66.81mA
2.41V     38.85mA    20.19mA    68.31mA
2.94V     43.21mA    20.19mA    76.64mA
3.6V      43.21mA    20.19mA    76.64mA
[Ramp]
dV/dt_r 777.92776mV/4.56537ns 534.21642mV/10.79401ns 970.12551mV/2.27008ns
dV/dt_f 800.59846mV/4.0546ns 504.71556mV/10.09764ns 1.00395V/2.04395ns
R_load = 50.0
| Removed startup time: 0s 0s 0s  .
| Removed end time: 44.9ns.
[Rising Waveform]
R_fixture   = 50.0
V_fixture   = 1.8V
V_fixture_min = 1.6V
V_fixture_max = 2.0V
0s        465.7mV    758.8mV    326.8mV
2.6ns     465.7mV    758.8mV    383.7mV
2.8ns     465.7mV    758.8mV    554.5mV
3.2ns     464.9mV    758.8mV    1.792V
3.8ns     482.1mV    758.8mV    1.982V
4.3ns     675.8mV    758.8mV    1.991V
4.9ns     1.656V     758.9mV    1.996V
5.5ns     1.782V     758.3mV    1.996V
9.2ns     1.798V     1.586V     1.999V
44.9ns    1.8V       1.6V       2V
| Removed startup time: 0s 0s 0s  .
| Removed end time: 199.9ns.
[Falling Waveform]
R_fixture   = 50.0
V_fixture   = 1.8V
V_fixture_min = 1.6V
V_fixture_max = 2.0V
0s        1.8V       1.6V       2V
4ns       1.806V     1.6V       2.003V
5.1ns     1.805V     1.602V     1.656V
6.8ns     1.788V     1.604V     789.4mV
8.4ns     1.607V     1.603V     458.3mV
12.9ns    734.4mV    1.556V     349.1mV
16.6ns    551.2mV    1.397V     333.8mV
24.9ns    480.1mV    957.4mV    327.4mV
38.9ns    466.7mV    791.7mV    326.7mV
199.9ns   465.7mV    758.8mV    326.8mV
| Removed startup time: 0s 0s 0s  .
| Removed end time: 199.9ns.
[Rising Waveform]
R_fixture   = 50.0
V_fixture   = 0V
V_fixture_min = 0V
V_fixture_max = 0V
0s        656.7nV    570.9nV    -420nV
3.2ns     210.9uV    668.8nV    -31.86mV
4.1ns     -6.048mV   1.126uV    87.13mV
6.9ns     58.43mV    -3.789mV   1.207V
8.4ns     265.4mV    -9.526mV   1.498V
12.3ns    957.7mV    36.31mV    1.601V
18.1ns    1.258V     331.1mV    1.616V
26.8ns    1.293V     726.1mV    1.617V
36.1ns    1.296V     855.2mV    1.617V
199.9ns   1.297V     890.4mV    1.617V
| Removed startup time: 0s 0s 0s  .
| Removed end time: 44.9ns.
[Falling Waveform]
R_fixture   = 50.0
V_fixture   = 0V
V_fixture_min = 0V
V_fixture_max = 0V
0s        1.297V     890.4mV    1.617V
2.1ns     1.297V     890.4mV    1.563V
2.4ns     1.296V     890.4mV    1.413V
3ns       1.29V      890.4mV    762.5mV
3.6ns     1.052V     890.5mV    215.6mV
4.4ns     519.6mV    891.6mV    14.9mV
5.9ns     28.06mV    702.4mV    2.235mV
7.6ns     3.792mV    225.2mV    970.6uV
10ns      1.368mV    9.77mV     491.9uV
44.9ns    423.4nV    34.7uV     451.9nV
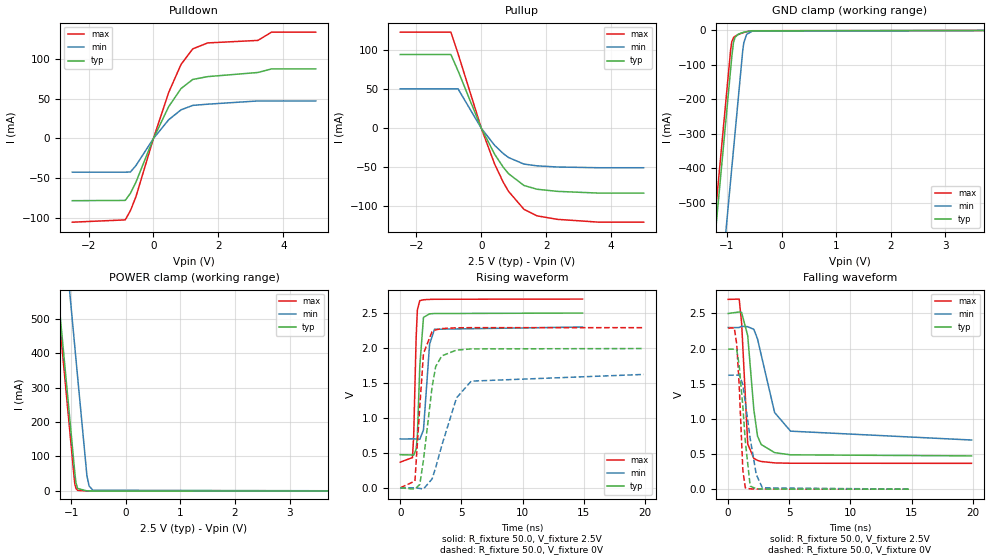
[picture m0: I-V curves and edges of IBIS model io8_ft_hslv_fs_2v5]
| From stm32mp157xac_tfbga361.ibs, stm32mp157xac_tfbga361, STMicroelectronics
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[Model]   io8_ft_hslv_fs_2v5
Model_type I/O
Polarity   Non-Inverting
Enable   Active-Low
| CAP_THRESHOLD on pad IOFT is "UDTCAPC" :
| Rising=20.00f vddiom   Falling=80.00f vddiom
| C_comp min and max val. don't necessarily correlate with the min and max pvt
| but are the smallest and greatest pad capacitance found.
| var   typ   min   max
C_comp   3.57714pF  3.54080pF  3.63508pF
|C_comp_pullup   2.11645pF  2.17895pF  2.03330pF
|C_comp_pulldown   1.46069pF  1.36185pF  1.60178pF
Vinl = 920.0mV
Vinh = 1.62V
Vmeas = 1.25V   | Reference voltage for timing measurements
Cref  = 50.0pF   | Timing specification test load capacitance value
Rref  = 100.0MOhm   | Timing specification test load resistance value
Vref  = 0V   | Timing specification test load voltage
[Model Spec]
| TIME_THRESHOLD on pin ZIV11 is "CMOS" :
| Rising=40.00f vdd   Falling=60.00f vdd
Vinl 1.03860V 964.60000mV 1.11860V
Vinh 1.36340V 1.26240V 1.44140V
| variable   typ   min   max
[Temperature Range] 25.0 140.0 -40.0
| variable   typ   min   max
[Voltage Range] 2.5V 2.3V 2.7V
| variable   typ   min   max
[POWER Clamp Reference] 2.5V 2.3V 2.7V
| variable   typ   min   max
[GND Clamp Reference] 0V 0V 0V
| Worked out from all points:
|   slope of the pulldown table from 0 to 0.375 V, typ, clamps not added: 11.3 ohm
|   slope of the pullup table from 0 to 0.375 V, typ, clamps not added: 12.3 ohm
|   GND clamp passes 1 mA (typ) near -0.52 V on its own axis
|   POWER clamp passes 1 mA (typ) near -0.83 V on its own axis
|   rising waveform, R_fixture 50.0, V_fixture 2.5V: 20-80 % time 257ps typ, 341ps min, 210ps max; typ from 0.473 V to 2.5 V
|   falling waveform, R_fixture 50.0, V_fixture 2.5V: 20-80 % time 627ps typ, 1.36ns min, 383ps max; typ from 2.5 V to 0.473 V
|   rising waveform, R_fixture 50.0, V_fixture 0V: 20-80 % time 832ps typ, 1.67ns min, 507ps max; typ from 0 V to 1.99 V
|   falling waveform, R_fixture 50.0, V_fixture 0V: 20-80 % time 549ps typ, 813ps min, 369ps max; typ from 1.99 V to 0 V
[POWER Clamp]
-2.5V     2.719A     3.084A     2.683A
-1.28V    644.8mA    1.01A      609.5mA
-1.26V    610.8mA    976.1mA    575.5mA
-1.04V    236.8mA    602.1mA    201.5mA
-940mV    66.83mA    432.1mA    31.5mA
-930mV    49.83mA    415.1mA    19.15mA
-910mV    22.88mA    381.1mA    7.077mA
-880mV    7.117mA    330.1mA    1.59mA
-710mV    9.523uA    43.89mA    337nA
-670mV    2.008uA    14.27mA    46.3nA
-600mV    132.9nA    1.998mA    1.599nA
5V        0A         0A         0A
[GND Clamp]
-2.5V     -2.779A    -3.101A    -2.723A
-1.26V    -670.8mA   -992.7mA   -614.5mA
-930mV    -109.8mA   -431.7mA   -53.54mA
-910mV    -75.83mA   -397.7mA   -32.67mA
-880mV    -35.28mA   -346.7mA   -21.39mA
-850mV    -20.07mA   -295.7mA   -16.99mA
-790mV    -10.9mA    -193.7mA   -12.02mA
-710mV    -6.374mA   -57.93mA   -7.219mA
-690mV    -5.545mA   -35.45mA   -6.225mA
-640mV    -3.775mA   -11.96mA   -4.068mA
-540mV    -1.354mA   -2.661mA   -1.223mA
5V        6.965nA    2.133uA    347.4pA
| variable   typ   min   max
[Pullup Reference] 2.5V 2.3V 2.7V
| variable   typ   min   max
[Pulldown Reference] 0V 0V 0V
[Pullup]
-2.5V     94.74mA    50.76mA    123.5mA
-940mV    94.74mA    50.76mA    123.5mA
-720mV    73.93mA    50.76mA    95.99mA
0V        9.19pA     1.4nA      5.79pA
410mV     -33.26mA   -21.8mA    -45.97mA
680mV     -50.15mA   -32.52mA   -69.57mA
840mV     -58.17mA   -37.44mA   -80.95mA
1.31V     -73.2mA    -45.74mA   -103.7mA
1.71V     -78mA      -48.02mA   -112.1mA
2.33V     -80.74mA   -49.51mA   -116.6mA
3.63V     -83.02mA   -50.48mA   -120.3mA
5V        -83.02mA   -50.48mA   -120.3mA
[Pulldown]
-2.5V     -78.63mA   -42.6mA    -105.8mA
-870mV    -78.28mA   -42.6mA    -102.9mA
-710mV    -69.32mA   -42.37mA   -91.24mA
-540mV    -55.23mA   -34.22mA   -73.64mA
0V        0A         -2pA       0A
470mV     40.29mA    23.69mA    58.27mA
850mV     63.07mA    36.18mA    93.59mA
1.21V     74.52mA    41.78mA    113.2mA
1.67V     78.14mA    43.3mA     120.7mA
3.22V     83.36mA    47.41mA    123.9mA
3.64V     87.89mA    47.41mA    134.4mA
5V        87.89mA    47.41mA    134.4mA
[Ramp]
dV/dt_r 1.19543V/829.73355ps 973.37325mV/1.67303ns 1.37488V/501.69225ps
dV/dt_f 1.21605V/621.74326ps 960.43981mV/1.3622ns 1.39952V/375.3242ps
R_load = 50.0
| Removed startup time: 0s 0s 0s  .
| Removed end time: 14.9ns.
[Rising Waveform]
R_fixture   = 50.0
V_fixture   = 2.5V
V_fixture_min = 2.3V
V_fixture_max = 2.7V
0s        473.2mV    699.2mV    367.5mV
1ns       470.2mV    699.4mV    432.4mV
1.1ns     466.3mV    699.4mV    748.4mV
1.3ns     554.5mV    699.2mV    2.147V
1.4ns     740.6mV    698.2mV    2.544V
1.6ns     1.743V     694.8mV    2.678V
1.9ns     2.438V     828.7mV    2.69V
2.4ns     2.489V     2.055V     2.695V
2.8ns     2.493V     2.268V     2.697V
14.9ns    2.5V       2.3V       2.7V
| Removed startup time: 0s 0s 0s  .
| Removed end time: 19.9ns.
[Falling Waveform]
R_fixture   = 50.0
V_fixture   = 2.5V
V_fixture_min = 2.3V
V_fixture_max = 2.7V
0s        2.5V       2.3V       2.7V
900ps     2.521V     2.3V       2.705V
1.1ns     2.514V     2.318V     2.368V
1.6ns     2.183V     2.312V     643.5mV
2.1ns     1.131V     2.274V     437.4mV
2.4ns     754.6mV    2.138V     409.7mV
2.7ns     635.6mV    1.911V     394.1mV
3.8ns     519.9mV    1.09V      373.7mV
5.1ns     488.6mV    825.5mV    368.9mV
19.9ns    473.3mV    699.3mV    367.5mV
| Removed startup time: 0s 0s 0s  .
| Removed end time: 19.9ns.
[Rising Waveform]
R_fixture   = 50.0
V_fixture   = 0V
V_fixture_min = 0V
V_fixture_max = 0V
0s        27.17nV    52.18nV    -3.877uV
1.2ns     -19.32mV   32.4uV     96.97mV
1.6ns     48.3mV     -8.846mV   1.167V
1.9ns     398mV      -16.15mV   1.922V
2.6ns     1.438V     125.7mV    2.234V
2.9ns     1.736V     289.9mV    2.259V
3.4ns     1.888V     607.4mV    2.278V
4.6ns     1.97V      1.286V     2.289V
5.8ns     1.987V     1.526V     2.291V
19.9ns    1.992V     1.622V     2.291V
| Removed startup time: 0s 0s 0s  .
| Removed end time: 14.9ns.
[Falling Waveform]
R_fixture   = 50.0
V_fixture   = 0V
V_fixture_min = 0V
V_fixture_max = 0V
0s        1.992V     1.622V     2.291V
500ps     1.992V     1.622V     2.296V
700ps     1.987V     1.622V     2.066V
900ps     1.762V     1.625V     1.485V
1.2ns     1.178V     1.488V     275.6mV
1.4ns     687mV      1.238V     18.6mV
1.8ns     43.97mV    720.9mV    4.208mV
2.3ns     4.885mV    206.8mV    2.373mV
2.8ns     2.765mV    18.59mV    1.602mV
14.9ns    11.62uV    36.23uV    3.055uV
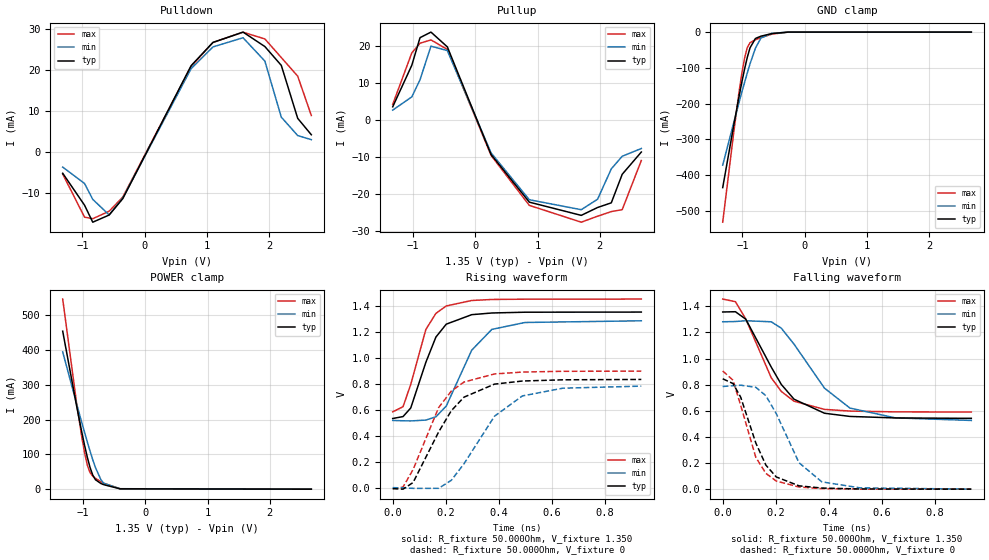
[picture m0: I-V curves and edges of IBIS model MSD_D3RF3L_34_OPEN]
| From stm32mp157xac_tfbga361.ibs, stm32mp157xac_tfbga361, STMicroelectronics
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[Model] MSD_D3RF3L_34_OPEN
Model_type   I/O
C_comp 2.572pF   2.485pF   2.698pF
Vinh = 810.000mV
Vinl = 540.000mV
Vmeas = 675.000mV
Vref = 675.000mV
[Model Spec]
Vinh   810.000mV   777.000mV   860.000mV
Vinl   540.000mV   507.000mV   590.000mV
Vmeas   675.000mV   642.000mV   725.000mV
Vref   675.000mV   642.000mV   725.000mV
[Temperature Range]   25.000   125.000   -40.000
[Voltage Range]   1.350V   1.283V   1.450V
[GND Clamp Reference]   0.00V   0.00V   0.00V
[Pulldown Reference]   0.00V   0.00V   0.00V
[POWER Clamp Reference]   1.350V   1.283V   1.450V
[Pullup Reference]   1.350V   1.283V   1.450V
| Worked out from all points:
|   slope of the pulldown table from 0 to 0.203 V, typ, clamps not added: 31 ohm
|   slope of the pullup table from 0 to 0.203 V, typ, clamps not added: 26.2 ohm
|   GND clamp passes 1 mA (typ) near -0.40 V on its own axis
|   POWER clamp passes 1 mA (typ) near -0.41 V on its own axis
|   rising waveform, R_fixture 50.000Ohm, V_fixture 1.350: 20-80 % time 86.5ps typ, 108ps min, 77.2ps max; typ from 0.532 V to 1.35 V
|   rising waveform, R_fixture 50.000Ohm, V_fixture 0: 20-80 % time 139ps typ, 161ps min, 125ps max; typ from -0.007 V to 0.832 V
|   falling waveform, R_fixture 50.000Ohm, V_fixture 1.350: 20-80 % time 140ps typ, 171ps min, 123ps max; typ from 1.36 V to 0.542 V
|   falling waveform, R_fixture 50.000Ohm, V_fixture 0: 20-80 % time 95.1ps typ, 115ps min, 84ps max; typ from 0.846 V to 0 V
[GND Clamp]
-1.318V   -435mA     -372.2mA   -531.7mA
-1.142V   -262.4mA   -254.2mA   -282.5mA
-1.055V   -179.8mA   -196.6mA   -167.2mA
-1.011V   -140.5mA   -168.4mA   -116mA
-966.7mV  -103.7mA   -140.9mA   -72.98mA
-922.7mV  -70.73mA   -114.2mA   -43.23mA
-878.8mV  -44.02mA   -88.84mA   -29.72mA
-790.9mV  -17.74mA   -44.62mA   -21.37mA
-703mV    -11.46mA   -16.55mA   -15.5mA
-527.3mV  -4.197mA   -3.553mA   -5.598mA
-263.6mV  -40.6uA    -78.9uA    -28.72uA
2.68V     28.25nA    782nA      4.355nA
[Power Clamp]
-1.33V    454.4mA    394.7mA    546.8mA
-1.111V   243.5mA    248.7mA    252.9mA
-1.023V   163.7mA    191.5mA    149.8mA
-978.8mV  126.5mA    163.6mA    105.2mA
-934.9mV  92.34mA    136.2mA    69.61mA
-890.9mV  62.88mA    109.8mA    47.89mA
-847mV    40.47mA    84.8mA     37.29mA
-803mV    27.03mA    61.92mA    31.1mA
-715.1mV  16.21mA    27.03mA    21.42mA
-671.2mV  12.92mA    16.88mA    17.18mA
-407.6mV  989.1uA    1.283mA    1.2mA
2.668V    -48.24nA   -903.5nA   -4.583nA
[Pulldown]
-1.318V   -5.3mA     -3.8mA     -5.5mA
-966.7mV  -13.1mA    -7.8mA     -16.01mA
-834.9mV  -17.24mA   -11.67mA   -16.39mA
-571.2mV  -15.49mA   -15.46mA   -14.56mA
-351.5mV  -11.48mA   -11.33mA   -11.1mA
747mV     20.95mA    20.23mA    20.78mA
1.098V    26.62mA    25.53mA    26.63mA
1.582V    29.15mA    27.77mA    29.12mA
1.933V    25.62mA    22.07mA    27.48mA
2.197V    21.03mA    8.4mA      22.94mA
2.461V    8.1mA      3.9mA      18.4mA
2.68V     4.1mA      2.9mA      8.8mA
[Pullup]
-1.33V    3.5mA      2.605mA    4.152mA
-1.023V   14.7mA     6.177mA    18.04mA
-890.9mV  22.15mA    10.8mA     20.65mA
-715.1mV  23.66mA    19.86mA    21.55mA
-451.5mV  19.67mA    18.67mA    18.98mA
251.5mV   -9.374mA   -8.925mA   -9.602mA
866.7mV   -22.22mA   -21.57mA   -23.09mA
1.702V    -25.79mA   -24.26mA   -27.63mA
1.965V    -23.66mA   -21.43mA   -26.01mA
2.185V    -22.41mA   -13.25mA   -24.77mA
2.361V    -14.7mA    -9.838mA   -24.24mA
2.668V    -8.7mA     -7.748mA   -10.98mA
[Ramp]
R_load=50.000Ohm
dV/dt_r   492.120mV/113.000ps  462.689mV/135.500ps  526.590mV/101.500ps
dV/dt_f   492.120mV/117.500ps  462.689mV/144.000ps  526.590mV/104.000ps
[Rising waveform]
R_fixture=50.000Ohm
V_fixture=1.350
V_fixture_min=1.283
V_fixture_max=1.450
0s        532mV      517.2mV    583mV
39ps      547mV      514.7mV    622.8mV
68ps      612.7mV    513.6mV    793.7mV
125ps     963.6mV    519.9mV    1.216V
163ps     1.158V     545.3mV    1.34V
202ps     1.257V     627.8mV    1.397V
298ps     1.33V      1.057V     1.439V
374ps     1.343V     1.217V     1.447V
499ps     1.349V     1.27V      1.449V
938ps     1.35V      1.283V     1.45V
[Rising waveform]
R_fixture=50.000Ohm
V_fixture=0
0s        -6.873mV   726.5uV    -6.057mV
39ps      -10.88mV   -866.8uV   5.005mV
77ps      40.4mV     -4.57mV    140.4mV
173ps     427.6mV    -4.508mV   615.1mV
221ps     592mV      57.02mV    742.2mV
269ps     696.2mV    184.3mV    812.4mV
384ps     796.3mV    549.7mV    874.5mV
489ps     820.1mV    705.5mV    889.1mV
642ps     829.5mV    765.2mV    894.9mV
938ps     832.3mV    780.9mV    896mV
[Falling waveform]
R_fixture=50.000Ohm
V_fixture=1.350
V_fixture_min=1.283
V_fixture_max=1.450
0s        1.357V     1.282V     1.456V
48ps      1.359V     1.284V     1.436V
87ps      1.302V     1.29V      1.303V
183ps     935.6mV    1.282V     853.7mV
221ps     802.4mV    1.233V     748.7mV
269ps     689.1mV    1.111V     673.6mV
384ps     581.5mV    773.6mV    611mV
480ps     557.1mV    621mV      598.1mV
652ps     545.5mV    545.9mV    591.9mV
938ps     542.3mV    526.3mV    590.8mV
[Falling waveform]
R_fixture=50.000Ohm
V_fixture=0
0s        845.5mV    786.3mV    905.1mV
39ps      808.9mV    792.2mV    834.6mV
68ps      703.6mV    796.1mV    640.6mV
125ps     353mV      780.1mV    243.1mV
163ps     183.8mV    715.7mV    120.9mV
202ps     93.67mV    578.7mV    62.01mV
288ps     25.49mV    202.2mV    16.43mV
374ps     8.467mV    55.91mV    4.573mV
518ps     1.43mV     10.13mV    531uV
938ps     30.59uV    161.7uV    5.632uV
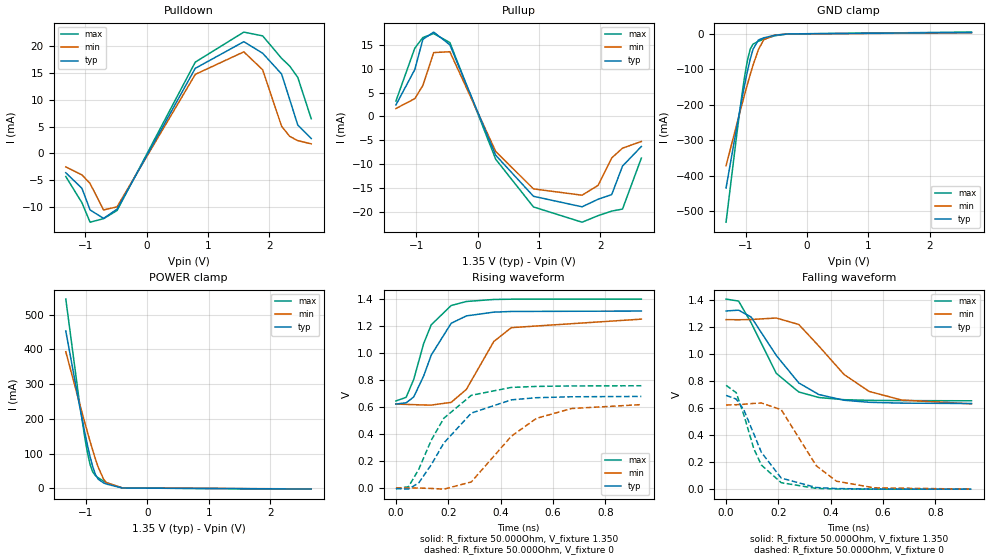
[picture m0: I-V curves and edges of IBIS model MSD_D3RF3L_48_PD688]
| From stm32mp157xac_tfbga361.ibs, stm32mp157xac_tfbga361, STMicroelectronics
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[Model] MSD_D3RF3L_48_PD688
Model_type   I/O
C_comp 2.452pF   2.367pF   2.576pF
Vinh = 810.000mV
Vinl = 540.000mV
Vmeas = 675.000mV
Vref = 675.000mV
[Model Spec]
Vinh   810.000mV   777.000mV   860.000mV
Vinl   540.000mV   507.000mV   590.000mV
Vmeas   675.000mV   642.000mV   725.000mV
Vref   675.000mV   642.000mV   725.000mV
[Temperature Range]   25.000   125.000   -40.000
[Voltage Range]   1.350V   1.283V   1.450V
[GND Clamp Reference]   0.00V   0.00V   0.00V
[Pulldown Reference]   0.00V   0.00V   0.00V
[POWER Clamp Reference]   1.350V   1.283V   1.450V
[Pullup Reference]   1.350V   1.283V   1.450V
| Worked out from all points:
|   slope of the pulldown table from 0 to 0.203 V, typ, clamps not added: 42.2 ohm
|   slope of the pullup table from 0 to 0.203 V, typ, clamps not added: 34.5 ohm
|   GND clamp passes 1 mA (typ) near -0.40 V on its own axis
|   POWER clamp passes 1 mA (typ) near -0.41 V on its own axis
|   rising waveform, R_fixture 50.000Ohm, V_fixture 1.350: 20-80 % time 95.3ps typ, 118ps min, 81.3ps max; typ from 0.623 V to 1.31 V
|   rising waveform, R_fixture 50.000Ohm, V_fixture 0: 20-80 % time 156ps typ, 187ps min, 134ps max; typ from -0.004 V to 0.68 V
|   falling waveform, R_fixture 50.000Ohm, V_fixture 1.350: 20-80 % time 157ps typ, 190ps min, 125ps max; typ from 1.32 V to 0.633 V
|   falling waveform, R_fixture 50.000Ohm, V_fixture 0: 20-80 % time 102ps typ, 121ps min, 84.9ps max; typ from 0.693 V to 0 V
[GND Clamp]
-1.318V   -434mA     -371.3mA   -530.2mA
-1.142V   -261.5mA   -253.5mA   -281.3mA
-1.055V   -179mA     -196mA     -166.2mA
-1.011V   -139.8mA   -167.8mA   -115.1mA
-966.7mV  -103mA     -140.4mA   -72.11mA
-922.7mV  -70.13mA   -113.7mA   -42.44mA
-878.8mV  -43.47mA   -88.39mA   -29mA
-790.9mV  -17.29mA   -44.25mA   -20.79mA
-703mV    -11.11mA   -16.27mA   -15.06mA
-527.3mV  -4.042mA   -3.425mA   -5.39mA
-307.6mV  -133.2uA   -195.4uA   -121.4uA
2.68V     3.865mA    3.009mA    5.016mA
[Power Clamp]
-1.33V    453.1mA    393.5mA    545.2mA
-1.111V   242.6mA    247.9mA    251.8mA
-1.023V   163mA      190.9mA    148.8mA
-978.8mV  125.7mA    162.9mA    104.3mA
-934.9mV  91.65mA    135.6mA    68.75mA
-890.9mV  62.25mA    109.3mA    47.1mA
-847mV    39.9mA     84.29mA    36.58mA
-803mV    26.52mA    61.46mA    30.46mA
-715.1mV  15.81mA    26.66mA    20.93mA
-671.2mV  12.58mA    16.56mA    16.75mA
-407.6mV  927uA      1.209mA    1.127mA
2.668V    -1.945mA   -1.621mA   -2.312mA
[Pulldown]
-1.318V   -3.6mA     -2.5mA     -4.3mA
-1.055V   -6.5mA     -4mA       -9.2mA
-922.7mV  -10.54mA   -5.6mA     -12.83mA
-703mV    -12.12mA   -10.54mA   -12.17mA
-483.3mV  -10.4mA    -9.97mA    -10.65mA
790.9mV   15.9mA     14.77mA    17.06mA
1.582V    20.88mA    18.98mA    22.67mA
1.889V    18.72mA    15.63mA    21.96mA
2.197V    14.84mA    5.1mA      17.77mA
2.329V    10.1mA     3.2mA      16.33mA
2.461V    5.3mA      2.4mA      14.2mA
2.68V     2.8mA      1.8mA      6.5mA
[Pullup]
-1.33V    2.4mA      1.652mA    3.207mA
-1.023V   9.8mA      3.715mA    14.27mA
-890.9mV  16.12mA    6.482mA    16.52mA
-715.1mV  17.65mA    13.36mA    17.34mA
-451.5mV  14.99mA    13.54mA    15.46mA
295.4mV   -8.125mA   -7.33mA    -8.964mA
910.6mV   -16.72mA   -15.17mA   -18.95mA
1.702V    -18.92mA   -16.49mA   -22.14mA
1.965V    -17.33mA   -14.42mA   -20.77mA
2.185V    -16.37mA   -8.694mA   -19.82mA
2.361V    -10.4mA    -6.643mA   -19.39mA
2.668V    -6.3mA     -5.248mA   -8.721mA
[Ramp]
R_load=50.000Ohm
dV/dt_r   408.330mV/126.000ps  374.999mV/155.000ps  452.370mV/108.000ps
dV/dt_f   408.330mV/130.000ps  375.029mV/157.500ps  452.370mV/105.500ps
[Rising waveform]
R_fixture=50.000Ohm
V_fixture=1.350
V_fixture_min=1.283
V_fixture_max=1.450
0s        623.3mV    623mV      646.3mV
39ps      632.5mV    620.7mV    673mV
68ps      675.8mV    618.8mV    805.9mV
106ps     831.5mV    616.4mV    1.072V
135ps     986.3mV    615.5mV    1.211V
211ps     1.222V     635.7mV    1.354V
269ps     1.277V     731.5mV    1.384V
374ps     1.305V     1.087V     1.399V
441ps     1.31V      1.19V      1.401V
938ps     1.313V     1.253V     1.402V
[Rising waveform]
R_fixture=50.000Ohm
V_fixture=0
0s        -4.244mV   700.6uV    -3.913mV
48ps      -7.622mV   803.3uV    9.712mV
87ps      38.06mV    135.8uV    137.9mV
135ps     173mV      -2.727mV   354.8mV
183ps     333.7mV    -8.1mV     517.8mV
288ps     556mV      45.38mV    688.2mV
441ps     654.3mV    384.5mV    746.6mV
537ps     670.3mV    517mV      754.1mV
671ps     677.2mV    590.1mV    757.4mV
938ps     679.7mV    619.1mV    759.1mV
[Falling waveform]
R_fixture=50.000Ohm
V_fixture=1.350
V_fixture_min=1.283
V_fixture_max=1.450
0s        1.317V     1.253V     1.405V
48ps      1.323V     1.252V     1.39V
96ps      1.272V     1.254V     1.229V
192ps     988.2mV    1.265V     855.9mV
278ps     785.1mV    1.217V     718.3mV
355ps     699.1mV    1.057V     677.3mV
451ps     657.3mV    847.5mV    661.2mV
547ps     642mV      722.3mV    656.5mV
671ps     635.8mV    658.8mV    654.4mV
938ps     633.1mV    630.3mV    653.2mV
[Falling waveform]
R_fixture=50.000Ohm
V_fixture=0
0s        692.9mV    621.9mV    767.7mV
39ps      665.9mV    624mV      712.8mV
68ps      586.4mV    627.5mV    549.2mV
106ps     408.6mV    633.9mV    299.3mV
135ps     272.2mV    637.1mV    178.2mV
211ps     81.68mV    587.3mV    47.64mV
345ps     12.04mV    172.4mV    5.744mV
422ps     4.414mV    58.76mV    1.747mV
566ps     693.9uV    10.12mV    289uV
938ps     28.97uV    215.8uV    -7.137uV
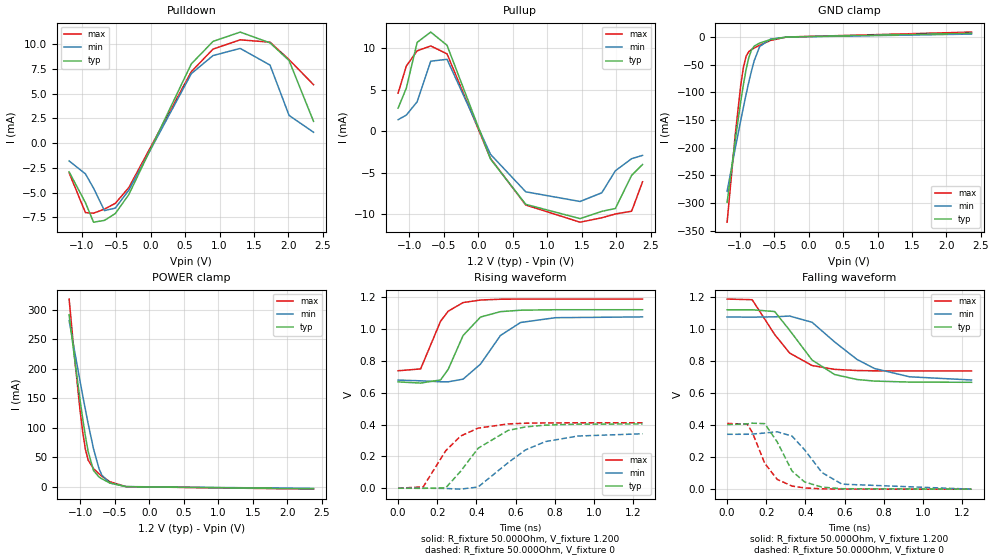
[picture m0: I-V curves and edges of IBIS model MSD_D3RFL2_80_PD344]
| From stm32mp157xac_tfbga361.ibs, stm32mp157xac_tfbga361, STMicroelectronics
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[Model] MSD_D3RFL2_80_PD344
Model_type   I/O
C_comp 2.341pF   2.257pF   2.465pF
Vinh = 820.000mV
Vinl = 380.000mV
Vmeas = 600.000mV
Vref = 600.000mV
[Model Spec]
Vinh   820.000mV   790.000mV   870.000mV
Vinl   380.000mV   350.000mV   430.000mV
Vmeas   600.000mV   570.000mV   650.000mV
Vref   600.000mV   570.000mV   650.000mV
[Temperature Range]   25.000   125.000   -40.000
[Voltage Range]   1.200V   1.140V   1.300V
[GND Clamp Reference]   0.00V   0.00V   0.00V
[Pulldown Reference]   0.00V   0.00V   0.00V
[POWER Clamp Reference]   1.200V   1.140V   1.300V
[Pullup Reference]   1.200V   1.140V   1.300V
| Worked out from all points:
|   slope of the pulldown table from 0 to 0.18 V, typ, clamps not added: 63.6 ohm
|   slope of the pullup table from 0 to 0.18 V, typ, clamps not added: 52.8 ohm
|   GND clamp passes 1 mA (typ) near -0.40 V on its own axis
|   POWER clamp passes 1 mA (typ) near -0.42 V on its own axis
|   rising waveform, R_fixture 50.000Ohm, V_fixture 1.200: 20-80 % time 113ps typ, 149ps min, 97.2ps max; typ from 0.668 V to 1.12 V
|   rising waveform, R_fixture 50.000Ohm, V_fixture 0: 20-80 % time 179ps typ, 225ps min, 151ps max; typ from 0 V to 0.404 V
|   falling waveform, R_fixture 50.000Ohm, V_fixture 1.200: 20-80 % time 183ps typ, 261ps min, 161ps max; typ from 1.12 V to 0.668 V
|   falling waveform, R_fixture 50.000Ohm, V_fixture 0: 20-80 % time 110ps typ, 142ps min, 99.7ps max; typ from 0.404 V to 0 V
[GND Clamp]
-1.182V   -298.7mA   -278.9mA   -334.7mA
-1.064V   -186.5mA   -201.2mA   -176.5mA
-984.9mV  -117.2mA   -151.1mA   -87.71mA
-945.5mV  -85.91mA   -126.8mA   -54.95mA
-906.1mV  -58.56mA   -103.4mA   -34.88mA
-866.7mV  -37.08mA   -81.29mA   -26.52mA
-827.3mV  -23.32mA   -60.76mA   -22.77mA
-787.9mV  -16.51mA   -42.62mA   -20mA
-709.1mV  -11.08mA   -17.24mA   -14.98mA
-551.5mV  -4.681mA   -3.974mA   -6.287mA
-315.1mV  -154.2uA   -220.1uA   -140.9uA
2.364V    6.653mA    5.111mA    8.718mA
[Power Clamp]
-1.164V   291.4mA    281.7mA    318.1mA
-1.085V   217.8mA    230mA      219mA
-1.006V   147.7mA    179.3mA    130.2mA
-966.7mV  115.2mA    154.5mA    92.47mA
-927.3mV  85.46mA    130.3mA    63.19mA
-887.9mV  59.77mA    106.8mA    45.13mA
-809.1mV  27.31mA    63.82mA    30.53mA
-730.3mV  16.63mA    30.75mA    21.92mA
-690.9mV  13.57mA    19.97mA    18.11mA
-572.7mV  6.421mA    6.328mA    8.512mA
-336.4mV  165.6uA    318.9uA    193uA
2.382V    -3.424mA   -2.825mA   -4.062mA
[Pulldown]
-1.182V   -2.9mA     -1.8mA     -3mA
-945.5mV  -6.01mA    -3.1mA     -7.01mA
-827.3mV  -7.98mA    -4.55mA    -7.07mA
-669.7mV  -7.8mA     -6.81mA    -6.66mA
-512.1mV  -7.108mA   -6.558mA   -6.078mA
-315.1mV  -5.18mA    -4.738mA   -4.478mA
590.9mV   8.002mA    7.016mA    7.22mA
906.1mV   10.27mA    8.842mA    9.491mA
1.3V      11.21mA    9.562mA    10.43mA
1.733V    10.12mA    7.88mA     10.19mA
2.009V    8.34mA     2.8mA      8.43mA
2.364V    2.2mA      1.1mA      5.9mA
[Pullup]
-1.164V   2.8mA      1.405mA    4.608mA
-1.045V   5.2mA      1.957mA    7.869mA
-887.9mV  10.72mA    3.566mA    9.704mA
-690.9mV  11.96mA    8.455mA    10.29mA
-454.5mV  10.37mA    8.679mA    9.337mA
175.8mV   -3.334mA   -2.766mA   -3.264mA
687.9mV   -8.798mA   -7.289mA   -8.88mA
1.476V    -10.52mA   -8.454mA   -10.95mA
1.791V    -9.644mA   -7.405mA   -10.42mA
1.988V    -9.3mA     -4.754mA   -9.962mA
2.224V    -5.3mA     -3.295mA   -9.625mA
2.382V    -4mA       -2.9mA     -6.085mA
[Ramp]
R_load=50.000Ohm
dV/dt_r   256.980mV/146.000ps  221.939mV/189.000ps  258.120mV/124.500ps
dV/dt_f   256.980mV/147.500ps  221.909mV/204.000ps  258.120mV/131.000ps
[Rising waveform]
R_fixture=50.000Ohm
V_fixture=1.200
V_fixture_min=1.140
V_fixture_max=1.300
0s        667.9mV    679.1mV    737.9mV
115ps     660.5mV    674.8mV    749.4mV
217ps     680.3mV    668.7mV    1.049V
256ps     747.1mV    668.4mV    1.112V
332ps     959mV      685.1mV    1.166V
421ps     1.075V     779.6mV    1.182V
523ps     1.109V     959.4mV    1.187V
626ps     1.118V     1.041V     1.188V
804ps     1.121V     1.071V     1.188V
1.249ns   1.121V     1.076V     1.188V
[Rising waveform]
R_fixture=50.000Ohm
V_fixture=0
0s        150uV      105.6uV    351.4uV
128ps     -467.5uV   541.8uV    8.433mV
243ps     2.087mV    -1.352mV   235.2mV
319ps     105.9mV    -5.686mV   327.8mV
409ps     251.5mV    8.039mV    377.7mV
562ps     363.3mV    160.6mV    404mV
651ps     385.2mV    240.8mV    408.4mV
753ps     396.5mV    293.2mV    410.2mV
919ps     402.5mV    328mV      411mV
1.249ns   403.8mV    342.1mV    411.2mV
[Falling waveform]
R_fixture=50.000Ohm
V_fixture=1.200
V_fixture_min=1.140
V_fixture_max=1.300
0s        1.121V     1.076V     1.188V
128ps     1.121V     1.075V     1.184V
243ps     1.11V      1.077V     966.7mV
319ps     993.9mV    1.082V     850.9mV
434ps     807mV      1.043V     772.6mV
549ps     716.6mV    920.5mV    748.7mV
664ps     685.2mV    810.5mV    741.4mV
753ps     675.5mV    754.1mV    739.5mV
932ps     669.2mV    702.3mV    738.7mV
1.249ns   667.8mV    682.2mV    738.6mV
[Falling waveform]
R_fixture=50.000Ohm
V_fixture=0
0s        403.6mV    342.9mV    410.9mV
103ps     407.9mV    343.1mV    406mV
128ps     412.4mV    344.3mV    356.6mV
192ps     409.4mV    351mV      161.9mV
256ps     295.2mV    358.7mV    60.91mV
332ps     112.6mV    331.4mV    19.29mV
396ps     45.09mV    245.7mV    7.6mV
485ps     12.67mV    103.6mV    2.062mV
587ps     2.828mV    31.26mV    388.6uV
1.249ns   -3.817uV   6.319uV    5.281uV
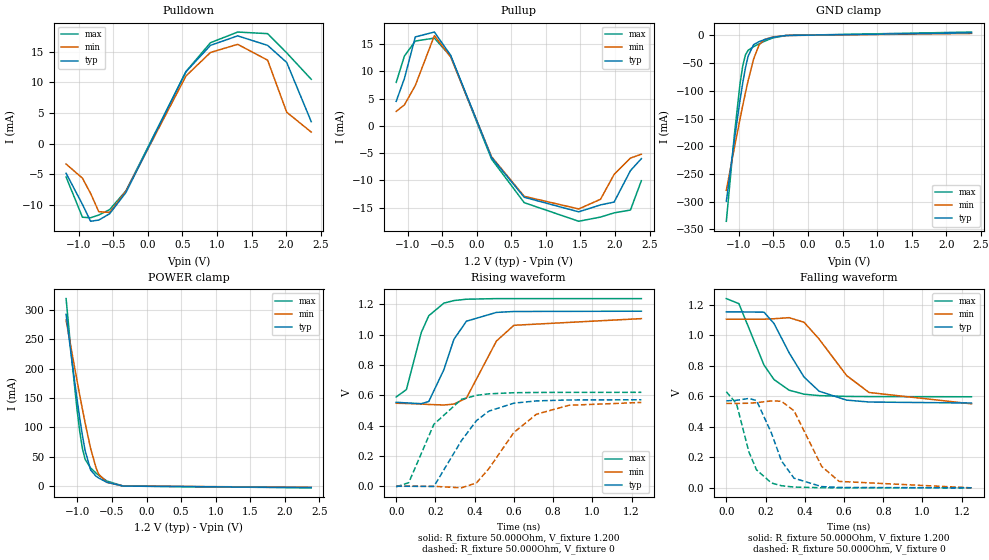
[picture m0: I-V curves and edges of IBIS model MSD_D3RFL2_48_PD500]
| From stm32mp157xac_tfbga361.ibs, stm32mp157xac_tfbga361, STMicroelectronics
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[Model] MSD_D3RFL2_48_PD500
Model_type   I/O
C_comp 2.418pF   2.333pF   2.542pF
Vinh = 820.000mV
Vinl = 380.000mV
Vmeas = 600.000mV
Vref = 600.000mV
[Model Spec]
Vinh   820.000mV   790.000mV   870.000mV
Vinl   380.000mV   350.000mV   430.000mV
Vmeas   600.000mV   570.000mV   650.000mV
Vref   600.000mV   570.000mV   650.000mV
[Temperature Range]   25.000   125.000   -40.000
[Voltage Range]   1.200V   1.140V   1.300V
[GND Clamp Reference]   0.00V   0.00V   0.00V
[Pulldown Reference]   0.00V   0.00V   0.00V
[POWER Clamp Reference]   1.200V   1.140V   1.300V
[Pullup Reference]   1.200V   1.140V   1.300V
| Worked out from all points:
|   slope of the pulldown table from 0 to 0.18 V, typ, clamps not added: 41.6 ohm
|   slope of the pullup table from 0 to 0.18 V, typ, clamps not added: 36.3 ohm
|   GND clamp passes 1 mA (typ) near -0.40 V on its own axis
|   POWER clamp passes 1 mA (typ) near -0.41 V on its own axis
|   rising waveform, R_fixture 50.000Ohm, V_fixture 1.200: 20-80 % time 101ps typ, 130ps min, 87.1ps max; typ from 0.554 V to 1.16 V
|   rising waveform, R_fixture 50.000Ohm, V_fixture 0: 20-80 % time 170ps typ, 204ps min, 144ps max; typ from 0.001 V to 0.571 V
|   falling waveform, R_fixture 50.000Ohm, V_fixture 1.200: 20-80 % time 169ps typ, 217ps min, 134ps max; typ from 1.15 V to 0.556 V
|   falling waveform, R_fixture 50.000Ohm, V_fixture 0: 20-80 % time 104ps typ, 130ps min, 88ps max; typ from 0.57 V to 0 V
[GND Clamp]
-1.182V   -299.2mA   -279.4mA   -335.3mA
-1.064V   -187.1mA   -201.6mA   -177.2mA
-984.9mV  -117.6mA   -151.5mA   -88.27mA
-945.5mV  -86.31mA   -127.1mA   -55.47mA
-906.1mV  -58.92mA   -103.8mA   -35.36mA
-866.7mV  -37.41mA   -81.56mA   -26.95mA
-787.9mV  -16.78mA   -42.84mA   -20.37mA
-709.1mV  -11.29mA   -17.41mA   -15.26mA
-630.3mV  -7.777mA   -7.464mA   -10.57mA
-512.1mV  -3.515mA   -2.998mA   -4.657mA
-315.1mV  -159.9uA   -226.2uA   -149.3uA
2.364V    4.576mA    3.518mA    5.996mA
[Power Clamp]
-1.164V   292.1mA    282.3mA    318.9mA
-1.085V   218.4mA    230.6mA    219.7mA
-1.006V   148.2mA    179.8mA    130.8mA
-966.7mV  115.7mA    154.9mA    93.06mA
-927.3mV  85.9mA     130.7mA    63.72mA
-887.9mV  60.18mA    107.2mA    45.62mA
-809.1mV  27.64mA    64.14mA    30.93mA
-730.3mV  16.89mA    31.01mA    22.25mA
-690.9mV  13.81mA    20.19mA    18.4mA
-572.7mV  6.565mA    6.472mA    8.682mA
-336.4mV  180.4uA    344.1uA    207.9uA
2.382V    -2.355mA   -1.942mA   -2.793mA
[Pulldown]
-1.182V   -4.8mA     -3.3mA     -5.4mA
-945.5mV  -9.87mA    -5.6mA     -11.96mA
-827.3mV  -12.62mA   -8.09mA    -12.05mA
-709.1mV  -12.42mA   -11.06mA   -11.6mA
-551.5mV  -11.39mA   -11.18mA   -10.72mA
-315.1mV  -7.913mA   -7.7mA     -7.643mA
551.5mV   11.72mA    11.03mA    11.75mA
906.1mV   16.02mA    14.86mA    16.45mA
1.3V      17.57mA    16.19mA    18.19mA
1.733V    16.02mA    13.61mA    17.93mA
2.009V    13.24mA    5.14mA     14.8mA
2.364V    3.6mA      1.9mA      10.5mA
[Pullup]
-1.164V   4.5mA      2.657mA    7.977mA
-1.045V   8.7mA      3.862mA    12.81mA
-887.9mV  16.31mA    7.401mA    15.55mA
-612.1mV  17.2mA     16.54mA    16.09mA
-375.8mV  12.93mA    12.63mA    12.73mA
215.2mV   -5.799mA   -5.653mA   -6.08mA
687.9mV   -13.08mA   -12.91mA   -14.07mA
1.476V    -15.75mA   -15.22mA   -17.48mA
1.791V    -14.48mA   -13.45mA   -16.71mA
1.988V    -13.96mA   -8.894mA   -15.94mA
2.224V    -8.2mA     -5.895mA   -15.42mA
2.382V    -6mA       -5.195mA   -10.05mA
[Ramp]
R_load=50.000Ohm
dV/dt_r   351.030mV/136.000ps  333.509mV/167.000ps  378.240mV/116.000ps
dV/dt_f   351.060mV/138.000ps  333.478mV/175.000ps  378.240mV/111.000ps
[Rising waveform]
R_fixture=50.000Ohm
V_fixture=1.200
V_fixture_min=1.140
V_fixture_max=1.300
0s        554.2mV    547.9mV    589.3mV
52ps      550.2mV    546.4mV    638.1mV
128ps     545.2mV    542.4mV    1.015V
166ps     559.2mV    539.8mV    1.125V
243ps     769.1mV    536.4mV    1.208V
294ps     968.7mV    542.4mV    1.225V
358ps     1.089V     582.1mV    1.234V
511ps     1.147V     958mV      1.238V
600ps     1.153V     1.062V     1.238V
1.25ns    1.155V     1.106V     1.238V
[Rising waveform]
R_fixture=50.000Ohm
V_fixture=0
0s        657.4uV    211.4uV    -3.713mV
64ps      283.6uV    627.9uV    24.53mV
192ps     -794.3uV   -76.27uV   408.8mV
332ps     299.9mV    -9.965mV   573.3mV
409ps     433.1mV    22.42mV    599.9mV
473ps     496.1mV    117.4mV    610mV
600ps     548.5mV    355.2mV    617.3mV
715ps     563.4mV    475.5mV    619mV
881ps     569.6mV    534.5mV    619.6mV
1.25ns    570.9mV    553.2mV    620mV
[Falling waveform]
R_fixture=50.000Ohm
V_fixture=1.200
V_fixture_min=1.140
V_fixture_max=1.300
0s        1.154V     1.106V     1.241V
64ps      1.154V     1.106V     1.208V
192ps     1.152V     1.106V     805.3mV
243ps     1.078V     1.109V     710.2mV
320ps     886.1mV    1.116V     640.4mV
396ps     726.5mV    1.086V     614.2mV
473ps     633.8mV    975.9mV    604.8mV
613ps     575.3mV    736.6mV    599.6mV
728ps     562.8mV    625.2mV    598.5mV
1.25ns    556.1mV    550.8mV    597.3mV
[Falling waveform]
R_fixture=50.000Ohm
V_fixture=0
0s        570.5mV    553.7mV    630mV
52ps      574.3mV    553.4mV    551.1mV
115ps     586.1mV    554.9mV    235.4mV
154ps     572.7mV    558.7mV    117.9mV
230ps     359.4mV    570.2mV    31.7mV
281ps     176.9mV    567.9mV    13.78mV
345ps     63.15mV    505.9mV    4.976mV
486ps     8.199mV    140.9mV    637.5uV
575ps     2.599mV    42.2mV     185.6uV
1.25ns    4.545uV    50.31uV    -546.2nV
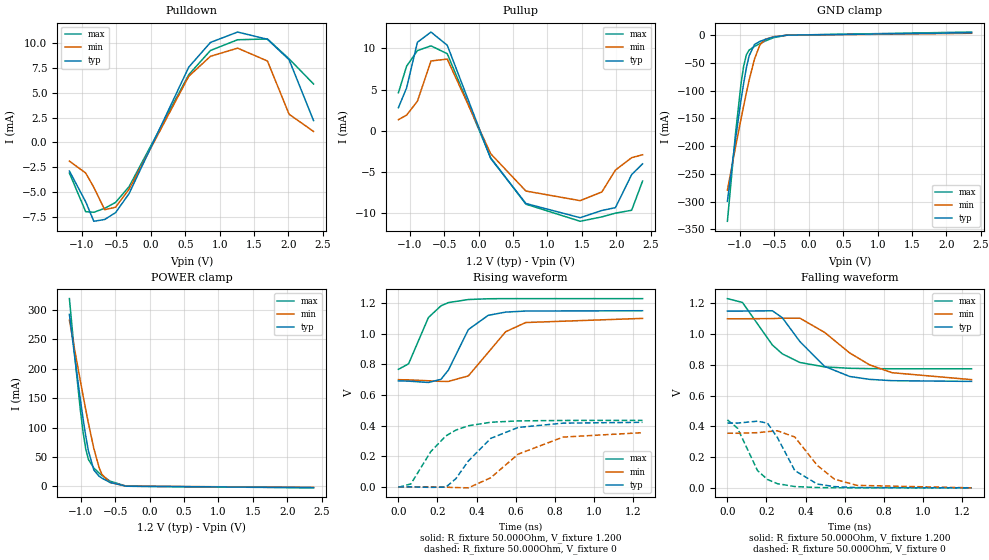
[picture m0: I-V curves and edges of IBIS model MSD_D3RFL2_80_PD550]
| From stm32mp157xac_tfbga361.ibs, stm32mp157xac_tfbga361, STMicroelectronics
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[Model] MSD_D3RFL2_80_PD550
Model_type   I/O
C_comp 2.431pF   2.345pF   2.556pF
Vinh = 820.000mV
Vinl = 380.000mV
Vmeas = 600.000mV
Vref = 600.000mV
[Model Spec]
Vinh   820.000mV   790.000mV   870.000mV
Vinl   380.000mV   350.000mV   430.000mV
Vmeas   600.000mV   570.000mV   650.000mV
Vref   600.000mV   570.000mV   650.000mV
[Temperature Range]   25.000   125.000   -40.000
[Voltage Range]   1.200V   1.140V   1.300V
[GND Clamp Reference]   0.00V   0.00V   0.00V
[Pulldown Reference]   0.00V   0.00V   0.00V
[POWER Clamp Reference]   1.200V   1.140V   1.300V
[Pullup Reference]   1.200V   1.140V   1.300V
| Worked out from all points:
|   slope of the pulldown table from 0 to 0.18 V, typ, clamps not added: 63.6 ohm
|   slope of the pullup table from 0 to 0.18 V, typ, clamps not added: 52.8 ohm
|   GND clamp passes 1 mA (typ) near -0.40 V on its own axis
|   POWER clamp passes 1 mA (typ) near -0.41 V on its own axis
|   rising waveform, R_fixture 50.000Ohm, V_fixture 1.200: 20-80 % time 115ps typ, 151ps min, 101ps max; typ from 0.692 V to 1.15 V
|   rising waveform, R_fixture 50.000Ohm, V_fixture 0: 20-80 % time 188ps typ, 233ps min, 162ps max; typ from 0 V to 0.421 V
|   falling waveform, R_fixture 50.000Ohm, V_fixture 1.200: 20-80 % time 195ps typ, 271ps min, 174ps max; typ from 1.15 V to 0.692 V
|   falling waveform, R_fixture 50.000Ohm, V_fixture 0: 20-80 % time 116ps typ, 148ps min, 107ps max; typ from 0.421 V to 0 V
[GND Clamp]
-1.182V   -299.4mA   -279.4mA   -335.5mA
-1.064V   -187.2mA   -201.7mA   -177.2mA
-984.9mV  -117.7mA   -151.5mA   -88.38mA
-945.5mV  -86.38mA   -127.3mA   -55.57mA
-906.1mV  -58.98mA   -103.8mA   -35.45mA
-866.7mV  -37.48mA   -81.61mA   -27.05mA
-787.9mV  -16.83mA   -42.88mA   -20.43mA
-709.1mV  -11.34mA   -17.45mA   -15.32mA
-630.3mV  -7.809mA   -7.49mA    -10.62mA
-512.1mV  -3.532mA   -3.013mA   -4.68mA
-315.1mV  -161.1uA   -227.4uA   -151.1uA
2.364V    4.162mA    3.192mA    5.446mA
[Power Clamp]
-1.164V   292.2mA    282.4mA    319.1mA
-1.085V   218.5mA    230.7mA    219.9mA
-1.006V   148.3mA    179.9mA    131mA
-966.7mV  115.8mA    155mA      93.19mA
-927.3mV  85.99mA    130.7mA    63.83mA
-887.9mV  60.26mA    107.3mA    45.72mA
-809.1mV  27.71mA    64.21mA    31.02mA
-730.3mV  16.94mA    31.06mA    22.31mA
-690.9mV  13.86mA    20.24mA    18.46mA
-572.7mV  6.594mA    6.506mA    8.718mA
-336.4mV  182.6uA    351.4uA    213.2uA
2.382V    -2.141mA   -1.766mA   -2.539mA
[Pulldown]
-1.182V   -2.9mA     -1.9mA     -3.1mA
-945.5mV  -6.01mA    -3.1mA     -7.01mA
-827.3mV  -7.98mA    -4.55mA    -7.07mA
-669.7mV  -7.8mA     -6.81mA    -6.67mA
-512.1mV  -7.11mA    -6.559mA   -6.078mA
-315.1mV  -5.18mA    -4.739mA   -4.478mA
551.5mV   7.601mA    6.677mA    6.842mA
866.7mV   10.1mA     8.7mA      9.288mA
1.261V    11.15mA    9.522mA    10.37mA
1.694V    10.42mA    8.225mA    10.45mA
2.009V    8.35mA     2.84mA     8.44mA
2.364V    2.2mA      1.1mA      5.9mA
[Pullup]
-1.164V   2.8mA      1.352mA    4.608mA
-1.045V   5.2mA      1.905mA    7.823mA
-887.9mV  10.72mA    3.587mA    9.714mA
-690.9mV  11.96mA    8.46mA     10.29mA
-454.5mV  10.36mA    8.682mA    9.336mA
175.8mV   -3.335mA   -2.766mA   -3.264mA
687.9mV   -8.798mA   -7.289mA   -8.88mA
1.476V    -10.52mA   -8.454mA   -10.95mA
1.791V    -9.643mA   -7.401mA   -10.42mA
1.988V    -9.3mA     -4.754mA   -9.967mA
2.224V    -5.3mA     -3.248mA   -9.615mA
2.382V    -4mA       -2.9mA     -6.085mA
[Ramp]
R_load=50.000Ohm
dV/dt_r   263.760mV/152.000ps  226.529mV/194.000ps  266.550mV/131.500ps
dV/dt_f   263.760mV/156.500ps  226.439mV/212.500ps  266.550mV/141.500ps
[Rising waveform]
R_fixture=50.000Ohm
V_fixture=1.200
V_fixture_min=1.140
V_fixture_max=1.300
0s        691.8mV    699.4mV    766.8mV
52ps      689.8mV    698mV      802.6mV
154ps     681.2mV    692.3mV    1.105V
218ps     701.6mV    688.3mV    1.181V
256ps     762mV      688.1mV    1.202V
358ps     1.026V     723.8mV    1.222V
460ps     1.119V     877.2mV    1.227V
549ps     1.14V      1.012V     1.228V
652ps     1.147V     1.072V     1.228V
1.25ns    1.149V     1.099V     1.228V
[Rising waveform]
R_fixture=50.000Ohm
V_fixture=0
0s        116.6uV    108.5uV    -2.408mV
64ps      561.6uV    379.6uV    19.76mV
166ps     -2.929mV   457.7uV    230.8mV
243ps     -1.185mV   -1.384mV   332.7mV
294ps     53.48mV    -4.318mV   370.4mV
358ps     168.8mV    -5.915mV   398.8mV
473ps     316.8mV    59.98mV    421.8mV
613ps     387.9mV    213.6mV    430.5mV
843ps     415.9mV    325mV      433.4mV
1.25ns    421.3mV    353.9mV    433.9mV
[Falling waveform]
R_fixture=50.000Ohm
V_fixture=1.200
V_fixture_min=1.140
V_fixture_max=1.300
0s        1.149V     1.099V     1.23V
77ps      1.149V     1.099V     1.205V
230ps     1.151V     1.1V       928.8mV
281ps     1.106V     1.103V     871.1mV
371ps     951mV      1.103V     814.7mV
498ps     789.1mV    1.01V      786.1mV
626ps     723.9mV    876.8mV    777mV
728ps     705.1mV    799.4mV    774.8mV
843ps     696.5mV    748.4mV    774mV
1.25ns    691.8mV    703.3mV    773.7mV
[Falling waveform]
R_fixture=50.000Ohm
V_fixture=0
0s        421mV      355mV      441.8mV
52ps      420.8mV    354.7mV    387.4mV
154ps     433.2mV    358.6mV    112.4mV
205ps     420.5mV    365.2mV    54.25mV
256ps     326.8mV    370.8mV    26.99mV
345ps     112.5mV    330.3mV    8.404mV
460ps     24.64mV    146.2mV    1.902mV
549ps     7.763mV    55.51mV    559.2uV
664ps     1.713mV    15.93mV    87.93uV
1.25ns    -1.614uV   14.77uV    6.207uV
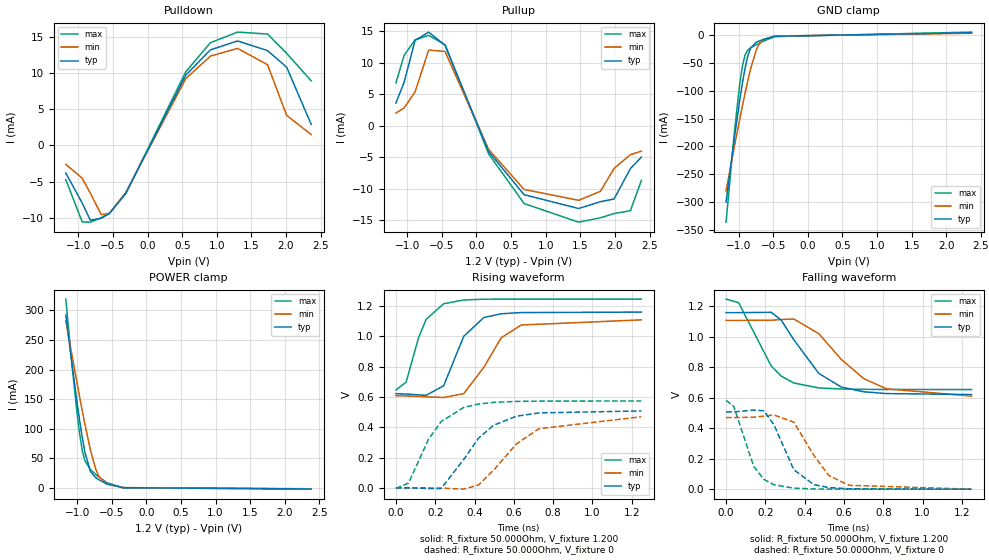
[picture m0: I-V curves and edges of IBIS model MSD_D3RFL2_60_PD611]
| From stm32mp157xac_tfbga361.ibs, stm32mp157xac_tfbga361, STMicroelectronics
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[Model] MSD_D3RFL2_60_PD611
Model_type   I/O
C_comp 2.448pF   2.362pF   2.573pF
Vinh = 820.000mV
Vinl = 380.000mV
Vmeas = 600.000mV
Vref = 600.000mV
[Model Spec]
Vinh   820.000mV   790.000mV   870.000mV
Vinl   380.000mV   350.000mV   430.000mV
Vmeas   600.000mV   570.000mV   650.000mV
Vref   600.000mV   570.000mV   650.000mV
[Temperature Range]   25.000   125.000   -40.000
[Voltage Range]   1.200V   1.140V   1.300V
[GND Clamp Reference]   0.00V   0.00V   0.00V
[Pulldown Reference]   0.00V   0.00V   0.00V
[POWER Clamp Reference]   1.200V   1.140V   1.300V
[Pullup Reference]   1.200V   1.140V   1.300V
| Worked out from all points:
|   slope of the pulldown table from 0 to 0.18 V, typ, clamps not added: 50.1 ohm
|   slope of the pullup table from 0 to 0.18 V, typ, clamps not added: 42.9 ohm
|   GND clamp passes 1 mA (typ) near -0.40 V on its own axis
|   POWER clamp passes 1 mA (typ) near -0.41 V on its own axis
|   rising waveform, R_fixture 50.000Ohm, V_fixture 1.200: 20-80 % time 109ps typ, 139ps min, 91.2ps max; typ from 0.621 V to 1.16 V
|   rising waveform, R_fixture 50.000Ohm, V_fixture 0: 20-80 % time 182ps typ, 223ps min, 152ps max; typ from 0 V to 0.508 V
|   falling waveform, R_fixture 50.000Ohm, V_fixture 1.200: 20-80 % time 190ps typ, 240ps min, 151ps max; typ from 1.16 V to 0.621 V
|   falling waveform, R_fixture 50.000Ohm, V_fixture 0: 20-80 % time 112ps typ, 138ps min, 95.5ps max; typ from 0.507 V to 0 V
[GND Clamp]
-1.182V   -299.5mA   -279.6mA   -335.7mA
-1.064V   -187.3mA   -201.7mA   -177.4mA
-984.9mV  -117.8mA   -151.5mA   -88.49mA
-945.5mV  -86.46mA   -127.3mA   -55.67mA
-906.1mV  -59.05mA   -103.8mA   -35.55mA
-866.7mV  -37.55mA   -81.66mA   -27.13mA
-827.3mV  -23.74mA   -61.1mA    -23.33mA
-748.5mV  -13.56mA   -28.1mA    -17.89mA
-709.1mV  -11.37mA   -17.48mA   -15.38mA
-630.3mV  -7.842mA   -7.517mA   -10.66mA
-472.7mV  -2.44mA    -2.145mA   -3.165mA
2.364V    3.741mA    2.874mA    4.907mA
[Power Clamp]
-1.164V   292.4mA    282.5mA    319.2mA
-1.085V   218.6mA    230.8mA    220mA
-1.006V   148.4mA    180mA      131.1mA
-966.7mV  115.9mA    155.1mA    93.3mA
-927.3mV  86.08mA    130.8mA    63.93mA
-887.9mV  60.35mA    107.3mA    45.81mA
-809.1mV  27.78mA    64.27mA    31.09mA
-730.3mV  17.01mA    31.11mA    22.38mA
-690.9mV  13.91mA    20.28mA    18.51mA
-572.7mV  6.625mA    6.535mA    8.753mA
-336.4mV  188.6uA    356.2uA    213.6uA
2.382V    -1.927mA   -1.589mA   -2.285mA
[Pulldown]
-1.182V   -3.8mA     -2.6mA     -4.7mA
-945.5mV  -7.91mA    -4.5mA     -10.52mA
-827.3mV  -10.3mA    -6.57mA    -10.56mA
-669.7mV  -10.02mA   -9.53mA    -9.94mA
-551.5mV  -9.375mA   -9.335mA   -9.299mA
-315.1mV  -6.567mA   -6.465mA   -6.608mA
551.5mV   9.675mA    9.198mA    10.14mA
906.1mV   13.16mA    12.3mA     14.14mA
1.3V      14.39mA    13.36mA    15.61mA
1.733V    13.06mA    11.12mA    15.34mA
2.009V    10.78mA    4.14mA     12.68mA
2.364V    2.9mA      1.5mA      8.9mA
[Pullup]
-1.164V   3.6mA      2.005mA    6.785mA
-1.045V   6.9mA      2.809mA    11.16mA
-887.9mV  13.51mA    5.344mA    13.61mA
-690.9mV  14.84mA    11.99mA    14.32mA
-454.5mV  12.73mA    11.77mA    12.85mA
175.8mV   -4.108mA   -3.772mA   -4.491mA
687.9mV   -10.95mA   -10.12mA   -12.35mA
1.476V    -13.14mA   -11.84mA   -15.31mA
1.791V    -12.06mA   -10.41mA   -14.61mA
1.988V    -11.63mA   -6.784mA   -13.94mA
2.224V    -6.8mA     -4.595mA   -13.48mA
2.382V    -5mA       -4.048mA   -8.7mA
[Ramp]
R_load=50.000Ohm
dV/dt_r   313.680mV/146.000ps  291.329mV/183.000ps  349.380mV/121.000ps
dV/dt_f   313.680mV/151.000ps  291.270mV/191.000ps  349.380mV/123.500ps
[Rising waveform]
R_fixture=50.000Ohm
V_fixture=1.200
V_fixture_min=1.140
V_fixture_max=1.300
0s        621.1mV    607.9mV    645.8mV
52ps      619.1mV    606.5mV    697.5mV
115ps     613.5mV    603.4mV    989.5mV
154ps     610.5mV    600.8mV    1.112V
243ps     673.8mV    596mV      1.214V
345ps     999mV      621.7mV    1.239V
447ps     1.123V     794.1mV    1.244V
536ps     1.148V     989.9mV    1.245V
638ps     1.156V     1.074V     1.245V
1.249ns   1.159V     1.108V     1.245V
[Rising waveform]
R_fixture=50.000Ohm
V_fixture=0
0s        176.9uV    137.1uV    -3.675mV
64ps      668.9uV    486.7uV    31.73mV
166ps     -4.063mV   577.7uV    321mV
230ps     -3.985mV   -1.113mV   437.4mV
345ps     187.5mV    -8.257mV   530.7mV
421ps     328.7mV    19.82mV    553.1mV
498ps     414mV      117.8mV    563.9mV
613ps     472.5mV    289.9mV    570.2mV
728ps     494.5mV    390.2mV    572.1mV
1.249ns   507.6mV    469.2mV    573.1mV
[Falling waveform]
R_fixture=50.000Ohm
V_fixture=1.200
V_fixture_min=1.140
V_fixture_max=1.300
0s        1.159V     1.108V     1.248V
64ps      1.159V     1.108V     1.224V
230ps     1.161V     1.109V     808.3mV
281ps     1.109V     1.114V     742.1mV
345ps     980.9mV    1.117V     696.9mV
472ps     759.8mV    1.021V     664.6mV
587ps     669.9mV    850.9mV    657.4mV
702ps     639.1mV    724.6mV    655.3mV
817ps     627.5mV    658.9mV    654.5mV
1.249ns   621.3mV    610.9mV    653.9mV
[Falling waveform]
R_fixture=50.000Ohm
V_fixture=0
0s        507.2mV    470.3mV    582.6mV
39ps      507mV      470mV      543.6mV
141ps     519.2mV    472.7mV    148.9mV
192ps     514.4mV    479.3mV    64.77mV
243ps     424.6mV    487.2mV    29.5mV
345ps     127.5mV    439.8mV    6.47mV
447ps     29.82mV    221mV      1.489mV
523ps     10.29mV    89.7mV     432.2uV
626ps     2.596mV    25.26mV    84.37uV
1.249ns   0V         19.61uV    -3.302uV
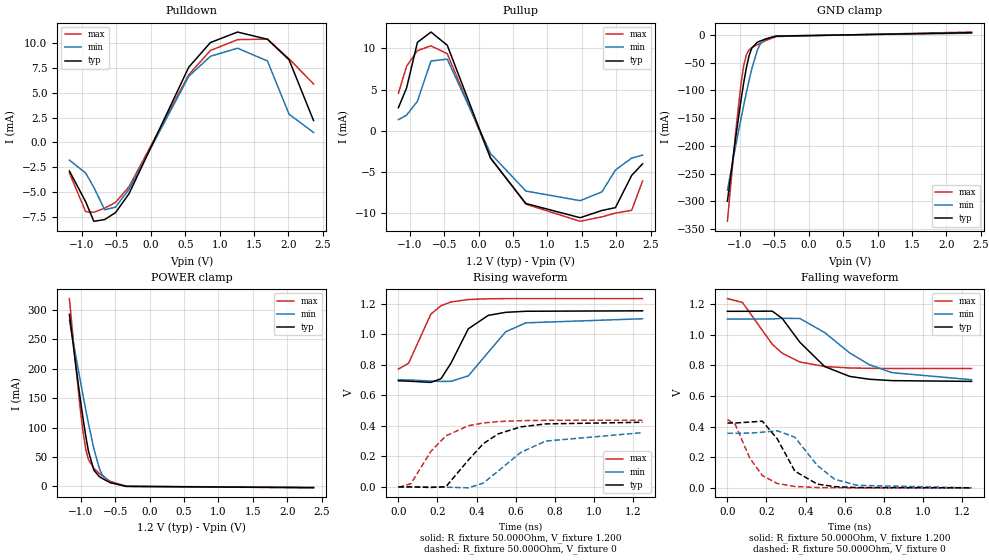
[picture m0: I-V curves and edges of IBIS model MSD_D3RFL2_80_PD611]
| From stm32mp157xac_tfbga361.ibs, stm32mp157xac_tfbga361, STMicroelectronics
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[Model] MSD_D3RFL2_80_PD611
Model_type   I/O
C_comp 2.448pF   2.362pF   2.573pF
Vinh = 820.000mV
Vinl = 380.000mV
Vmeas = 600.000mV
Vref = 600.000mV
[Model Spec]
Vinh   820.000mV   790.000mV   870.000mV
Vinl   380.000mV   350.000mV   430.000mV
Vmeas   600.000mV   570.000mV   650.000mV
Vref   600.000mV   570.000mV   650.000mV
[Temperature Range]   25.000   125.000   -40.000
[Voltage Range]   1.200V   1.140V   1.300V
[GND Clamp Reference]   0.00V   0.00V   0.00V
[Pulldown Reference]   0.00V   0.00V   0.00V
[POWER Clamp Reference]   1.200V   1.140V   1.300V
[Pullup Reference]   1.200V   1.140V   1.300V
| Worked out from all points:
|   slope of the pulldown table from 0 to 0.18 V, typ, clamps not added: 63.6 ohm
|   slope of the pullup table from 0 to 0.18 V, typ, clamps not added: 52.8 ohm
|   GND clamp passes 1 mA (typ) near -0.40 V on its own axis
|   POWER clamp passes 1 mA (typ) near -0.41 V on its own axis
|   rising waveform, R_fixture 50.000Ohm, V_fixture 1.200: 20-80 % time 116ps typ, 151ps min, 102ps max; typ from 0.696 V to 1.16 V
|   rising waveform, R_fixture 50.000Ohm, V_fixture 0: 20-80 % time 189ps typ, 235ps min, 164ps max; typ from 0 V to 0.424 V
|   falling waveform, R_fixture 50.000Ohm, V_fixture 1.200: 20-80 % time 197ps typ, 273ps min, 177ps max; typ from 1.15 V to 0.696 V
|   falling waveform, R_fixture 50.000Ohm, V_fixture 0: 20-80 % time 117ps typ, 149ps min, 109ps max; typ from 0.424 V to 0 V
[GND Clamp]
-1.182V   -299.5mA   -279.6mA   -335.7mA
-1.064V   -187.3mA   -201.7mA   -177.4mA
-984.9mV  -117.8mA   -151.5mA   -88.49mA
-945.5mV  -86.46mA   -127.3mA   -55.67mA
-906.1mV  -59.05mA   -103.8mA   -35.55mA
-866.7mV  -37.55mA   -81.66mA   -27.13mA
-827.3mV  -23.74mA   -61.1mA    -23.33mA
-748.5mV  -13.56mA   -28.1mA    -17.89mA
-709.1mV  -11.37mA   -17.48mA   -15.38mA
-630.3mV  -7.842mA   -7.517mA   -10.66mA
-472.7mV  -2.44mA    -2.145mA   -3.165mA
2.364V    3.741mA    2.874mA    4.907mA
[Power Clamp]
-1.164V   292.4mA    282.5mA    319.2mA
-1.085V   218.6mA    230.8mA    220mA
-1.006V   148.4mA    180mA      131.1mA
-966.7mV  115.9mA    155.1mA    93.3mA
-927.3mV  86.08mA    130.8mA    63.93mA
-887.9mV  60.35mA    107.3mA    45.81mA
-809.1mV  27.78mA    64.27mA    31.09mA
-730.3mV  17.01mA    31.11mA    22.38mA
-690.9mV  13.91mA    20.28mA    18.51mA
-572.7mV  6.625mA    6.535mA    8.753mA
-336.4mV  188.6uA    356.2uA    213.6uA
2.382V    -1.927mA   -1.589mA   -2.285mA
[Pulldown]
-1.182V   -2.9mA     -1.8mA     -3.1mA
-945.5mV  -6.01mA    -3.1mA     -7.01mA
-827.3mV  -7.98mA    -4.55mA    -7.07mA
-669.7mV  -7.81mA    -6.81mA    -6.66mA
-512.1mV  -7.105mA   -6.558mA   -6.074mA
-315.1mV  -5.18mA    -4.739mA   -4.478mA
551.5mV   7.6mA      6.678mA    6.842mA
866.7mV   10.09mA    8.7mA      9.29mA
1.261V    11.15mA    9.514mA    10.38mA
1.694V    10.42mA    8.229mA    10.44mA
2.009V    8.34mA     2.84mA     8.44mA
2.364V    2.2mA      1mA        5.9mA
[Pullup]
-1.164V   2.8mA      1.352mA    4.554mA
-1.045V   5.2mA      1.905mA    7.823mA
-887.9mV  10.71mA    3.587mA    9.709mA
-690.9mV  11.96mA    8.455mA    10.29mA
-454.5mV  10.36mA    8.679mA    9.337mA
175.8mV   -3.335mA   -2.766mA   -3.264mA
687.9mV   -8.799mA   -7.289mA   -8.88mA
1.476V    -10.52mA   -8.454mA   -10.95mA
1.791V    -9.643mA   -7.397mA   -10.42mA
1.988V    -9.3mA     -4.754mA   -9.962mA
2.224V    -5.4mA     -3.295mA   -9.625mA
2.382V    -4mA       -2.948mA   -6.085mA
[Ramp]
R_load=50.000Ohm
dV/dt_r   264.870mV/153.500ps  227.309mV/195.000ps  267.990mV/132.500ps
dV/dt_f   264.870mV/157.500ps  227.249mV/214.500ps  267.990mV/143.000ps
[Rising waveform]
R_fixture=50.000Ohm
V_fixture=1.200
V_fixture_min=1.140
V_fixture_max=1.300
0s        695.9mV    702.9mV    772.9mV
52ps      693.7mV    701.5mV    811.2mV
166ps     685.6mV    694.8mV    1.133V
218ps     709.4mV    691.7mV    1.188V
269ps     811.1mV    692.4mV    1.213V
358ps     1.037V     728.3mV    1.229V
460ps     1.125V     883.1mV    1.234V
549ps     1.145V     1.017V     1.235V
652ps     1.152V     1.076V     1.235V
1.25ns    1.155V     1.103V     1.235V
[Rising waveform]
R_fixture=50.000Ohm
V_fixture=0
0s        142.7uV    111.3uV    -2.527mV
64ps      577.7uV    384.1uV    21.13mV
166ps     -3.328mV   447.8uV    232.9mV
243ps     1.333mV    -1.435mV   334.7mV
358ps     175.8mV    -5.888mV   401.5mV
435ps     284.3mV    25.86mV    419.6mV
511ps     347.9mV    104.1mV    428.7mV
626ps     393.7mV    226mV      434.6mV
754ps     413.3mV    300.7mV    436.7mV
1.25ns    424.2mV    355.9mV    437.8mV
[Falling waveform]
R_fixture=50.000Ohm
V_fixture=1.200
V_fixture_min=1.140
V_fixture_max=1.300
0s        1.154V     1.103V     1.237V
77ps      1.154V     1.103V     1.212V
230ps     1.155V     1.104V     937.8mV
281ps     1.107V     1.108V     880mV
371ps     951.7mV    1.107V     822.7mV
498ps     792.8mV    1.015V     793.2mV
626ps     728.6mV    882.1mV    783.6mV
728ps     709.6mV    804.3mV    781.2mV
843ps     700.8mV    752.9mV    780.3mV
1.25ns    695.9mV    706.9mV    779.9mV
[Falling waveform]
R_fixture=50.000Ohm
V_fixture=0
0s        424mV      357.1mV    445.8mV
39ps      423.8mV    356.9mV    417.2mV
115ps     429.9mV    357.8mV    193.3mV
179ps     435.9mV    363.7mV    80.33mV
256ps     318.8mV    373mV      28.08mV
345ps     109.5mV    331.4mV    8.93mV
460ps     24.5mV     146.7mV    2.088mV
549ps     7.918mV    56.13mV    630.8uV
664ps     1.811mV    16.4mV     99.26uV
1.25ns    14.13uV    17.7uV     5.237uV
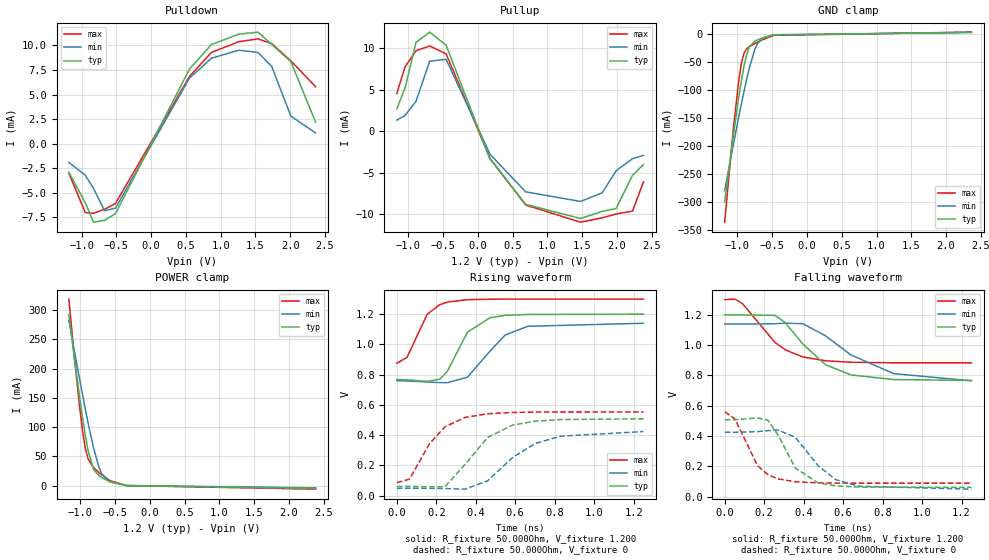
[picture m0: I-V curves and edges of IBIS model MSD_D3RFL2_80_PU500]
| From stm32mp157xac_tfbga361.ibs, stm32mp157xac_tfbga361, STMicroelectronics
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[Model] MSD_D3RFL2_80_PU500
Model_type   I/O
C_comp 2.422pF   2.336pF   2.548pF
Vinh = 820.000mV
Vinl = 380.000mV
Vmeas = 600.000mV
Vref = 600.000mV
[Model Spec]
Vinh   820.000mV   790.000mV   870.000mV
Vinl   380.000mV   350.000mV   430.000mV
Vmeas   600.000mV   570.000mV   650.000mV
Vref   600.000mV   570.000mV   650.000mV
[Temperature Range]   25.000   125.000   -40.000
[Voltage Range]   1.200V   1.140V   1.300V
[GND Clamp Reference]   0.00V   0.00V   0.00V
[Pulldown Reference]   0.00V   0.00V   0.00V
[POWER Clamp Reference]   1.200V   1.140V   1.300V
[Pullup Reference]   1.200V   1.140V   1.300V
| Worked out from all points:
|   slope of the pulldown table from 0 to 0.18 V, typ, clamps not added: 63.6 ohm
|   slope of the pullup table from 0 to 0.18 V, typ, clamps not added: 52.8 ohm
|   GND clamp passes 1 mA (typ) near -0.40 V on its own axis
|   POWER clamp passes 1 mA (typ) near -0.41 V on its own axis
|   rising waveform, R_fixture 50.000Ohm, V_fixture 1.200: 20-80 % time 110ps typ, 148ps min, 95.6ps max; typ from 0.768 V to 1.2 V
|   rising waveform, R_fixture 50.000Ohm, V_fixture 0: 20-80 % time 180ps typ, 226ps min, 152ps max; typ from 0.061 V to 0.508 V
|   falling waveform, R_fixture 50.000Ohm, V_fixture 1.200: 20-80 % time 204ps typ, 275ps min, 185ps max; typ from 1.2 V to 0.767 V
|   falling waveform, R_fixture 50.000Ohm, V_fixture 0: 20-80 % time 120ps typ, 157ps min, 113ps max; typ from 0.508 V to 0.061 V
[GND Clamp]
-1.182V   -299.2mA   -279.2mA   -335.4mA
-1.064V   -187mA     -201.4mA   -177mA
-984.9mV  -117.5mA   -151.3mA   -88.22mA
-945.5mV  -86.23mA   -127mA     -55.43mA
-906.1mV  -58.85mA   -103.7mA   -35.31mA
-866.7mV  -37.36mA   -81.45mA   -26.92mA
-827.3mV  -23.56mA   -60.91mA   -23.14mA
-748.5mV  -13.42mA   -27.95mA   -17.73mA
-709.1mV  -11.25mA   -17.35mA   -15.24mA
-630.3mV  -7.747mA   -7.41mA    -10.55mA
-472.7mV  -2.393mA   -2.09mA    -3.114mA
2.364V    2.273mA    1.921mA    2.674mA
[Power Clamp]
-1.164V   292.3mA    282.6mA    319mA
-1.085V   218.5mA    230.8mA    219.8mA
-1.006V   148.3mA    180mA      130.9mA
-966.7mV  115.8mA    155.2mA    93.11mA
-927.3mV  86mA       130.8mA    63.78mA
-887.9mV  60.28mA    107.3mA    45.68mA
-809.1mV  27.72mA    64.28mA    30.98mA
-730.3mV  16.96mA    31.12mA    22.29mA
-690.9mV  13.87mA    20.29mA    18.43mA
-572.7mV  6.606mA    6.547mA    8.709mA
-336.4mV  197.1uA    373.8uA    219.2uA
2.382V    -4.548mA   -3.619mA   -5.899mA
[Pulldown]
-1.182V   -2.9mA     -1.9mA     -3mA
-945.5mV  -6.01mA    -3.2mA     -7mA
-827.3mV  -7.98mA    -4.55mA    -7.07mA
-669.7mV  -7.8mA     -6.81mA    -6.67mA
-512.1mV  -7.11mA    -6.557mA   -6.074mA
551.5mV   7.6mA      6.678mA    6.842mA
866.7mV   10.09mA    8.7mA      9.291mA
1.261V    11.15mA    9.516mA    10.38mA
1.536V    11.36mA    9.29mA     10.67mA
1.733V    10.11mA    7.875mA    10.19mA
2.009V    8.35mA     2.81mA     8.44mA
2.364V    2.2mA      1.1mA      5.8mA
[Pullup]
-1.164V   2.7mA      1.352mA    4.554mA
-1.045V   5.2mA      1.905mA    7.769mA
-887.9mV  10.72mA    3.619mA    9.708mA
-690.9mV  11.96mA    8.455mA    10.29mA
-454.5mV  10.37mA    8.676mA    9.333mA
175.8mV   -3.334mA   -2.766mA   -3.264mA
687.9mV   -8.795mA   -7.289mA   -8.88mA
1.476V    -10.51mA   -8.451mA   -10.95mA
1.791V    -9.643mA   -7.398mA   -10.42mA
1.988V    -9.3mA     -4.754mA   -9.962mA
2.224V    -5.3mA     -3.295mA   -9.621mA
2.382V    -4mA       -2.9mA     -6.085mA
[Ramp]
R_load=50.000Ohm
dV/dt_r   264.084mV/146.000ps  227.043mV/188.500ps  264.612mV/124.000ps
dV/dt_f   264.084mV/162.500ps  227.010mV/221.000ps  264.612mV/149.500ps
[Rising waveform]
R_fixture=50.000Ohm
V_fixture=1.200
V_fixture_min=1.140
V_fixture_max=1.300
0s        767.5mV    759.8mV    875.2mV
52ps      765.6mV    758.3mV    914.6mV
154ps     755.4mV    751.8mV    1.199V
218ps     770mV      747.3mV    1.263V
256ps     822.3mV    746.8mV    1.28V
358ps     1.081V     783.2mV    1.296V
473ps     1.177V     957mV      1.299V
549ps     1.192V     1.062V     1.3V
664ps     1.198V     1.12V      1.3V
1.25ns    1.2V       1.14V      1.3V
[Rising waveform]
R_fixture=50.000Ohm
V_fixture=0
0s        60.59mV    48.58mV    85.49mV
64ps      60.89mV    48.76mV    108.9mV
166ps     58.07mV    48.63mV    343.5mV
243ps     57.85mV    46.86mV    453.9mV
345ps     205.6mV    42.72mV    516.8mV
460ps     384.8mV    97.87mV    541.6mV
588ps     466.9mV    253.4mV    550mV
703ps     492.6mV    345.6mV    552.4mV
830ps     503.1mV    393.1mV    553.1mV
1.25ns    508.2mV    423.8mV    553.4mV
[Falling waveform]
R_fixture=50.000Ohm
V_fixture=1.200
V_fixture_min=1.140
V_fixture_max=1.300
0s        1.2V       1.14V      1.301V
52ps      1.2V       1.14V      1.305V
90ps      1.2V       1.14V      1.275V
256ps     1.197V     1.142V     1.017V
307ps     1.148V     1.146V     969.7mV
396ps     1.008V     1.142V     922.2mV
511ps     870.9mV    1.062V     897.2mV
639ps     803.7mV    936.2mV    887.4mV
856ps     773.2mV    812.1mV    883.8mV
1.25ns    767.3mV    765mV      883.5mV
[Falling waveform]
R_fixture=50.000Ohm
V_fixture=0
0s        507.9mV    424.9mV    560.5mV
52ps      507.5mV    424.6mV    512.6mV
166ps     519.3mV    428.8mV    204.6mV
218ps     505.2mV    435.3mV    145.2mV
269ps     409.2mV    439.7mV    116.7mV
358ps     188.4mV    391.8mV    97.29mV
473ps     89.93mV    204.6mV    90.2mV
562ps     70.21mV    111.8mV    88.69mV
677ps     62.72mV    68.26mV    88.17mV
1.25ns    60.52mV    48.57mV    88.06mV
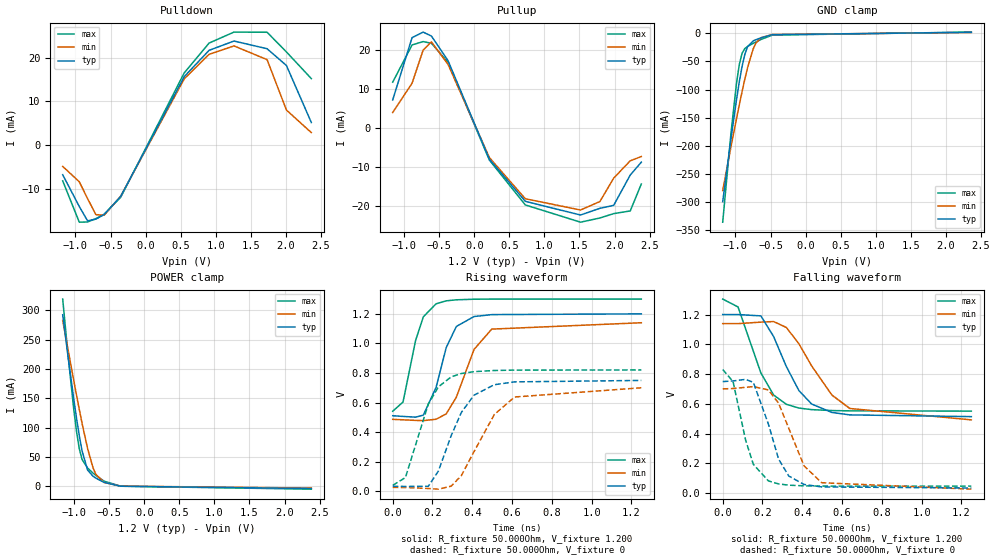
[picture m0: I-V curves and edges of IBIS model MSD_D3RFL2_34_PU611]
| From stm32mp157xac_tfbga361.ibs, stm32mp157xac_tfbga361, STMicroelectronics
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[Model] MSD_D3RFL2_34_PU611
Model_type   I/O
C_comp 2.451pF   2.364pF   2.578pF
Vinh = 820.000mV
Vinl = 380.000mV
Vmeas = 600.000mV
Vref = 600.000mV
[Model Spec]
Vinh   820.000mV   790.000mV   870.000mV
Vinl   380.000mV   350.000mV   430.000mV
Vmeas   600.000mV   570.000mV   650.000mV
Vref   600.000mV   570.000mV   650.000mV
[Temperature Range]   25.000   125.000   -40.000
[Voltage Range]   1.200V   1.140V   1.300V
[GND Clamp Reference]   0.00V   0.00V   0.00V
[Pulldown Reference]   0.00V   0.00V   0.00V
[POWER Clamp Reference]   1.200V   1.140V   1.300V
[Pullup Reference]   1.200V   1.140V   1.300V
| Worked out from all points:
|   slope of the pulldown table from 0 to 0.18 V, typ, clamps not added: 31.3 ohm
|   slope of the pullup table from 0 to 0.18 V, typ, clamps not added: 26.5 ohm
|   GND clamp passes 1 mA (typ) near -0.40 V on its own axis
|   POWER clamp passes 1 mA (typ) near -0.41 V on its own axis
|   rising waveform, R_fixture 50.000Ohm, V_fixture 1.200: 20-80 % time 88.5ps typ, 116ps min, 74.7ps max; typ from 0.512 V to 1.2 V
|   rising waveform, R_fixture 50.000Ohm, V_fixture 0: 20-80 % time 138ps typ, 170ps min, 118ps max; typ from 0.035 V to 0.75 V
|   falling waveform, R_fixture 50.000Ohm, V_fixture 1.200: 20-80 % time 153ps typ, 197ps min, 127ps max; typ from 1.2 V to 0.514 V
|   falling waveform, R_fixture 50.000Ohm, V_fixture 0: 20-80 % time 98.7ps typ, 125ps min, 84.5ps max; typ from 0.75 V to 0.035 V
[GND Clamp]
-1.182V   -299.4mA   -279.4mA   -335.7mA
-1.064V   -187.2mA   -201.7mA   -177.3mA
-984.9mV  -117.7mA   -151.5mA   -88.45mA
-945.5mV  -86.41mA   -127.2mA   -55.64mA
-906.1mV  -59.01mA   -103.9mA   -35.52mA
-866.7mV  -37.5mA    -81.58mA   -27.1mA
-827.3mV  -23.7mA    -61.03mA   -23.31mA
-748.5mV  -13.53mA   -28.05mA   -17.87mA
-709.1mV  -11.34mA   -17.43mA   -15.36mA
-630.3mV  -7.814mA   -7.472mA   -10.65mA
-472.7mV  -2.424mA   -2.118mA   -3.155mA
2.364V    1.86mA     1.572mA    2.188mA
[Power Clamp]
-1.164V   292.5mA    282.8mA    319.3mA
-1.085V   218.7mA    231.1mA    220.1mA
-1.006V   148.5mA    180.2mA    131.1mA
-966.7mV  116mA      155.3mA    93.34mA
-927.3mV  86.16mA    131mA      63.99mA
-887.9mV  60.42mA    107.5mA    45.87mA
-809.1mV  27.84mA    64.38mA    31.14mA
-730.3mV  17.05mA    31.2mA     22.42mA
-690.9mV  13.96mA    20.37mA    18.55mA
-572.7mV  6.658mA    6.592mA    8.774mA
-336.4mV  200.5uA    379.1uA    223.4uA
2.382V    -3.72mA    -2.96mA    -4.821mA
[Pulldown]
-1.182V   -6.7mA     -4.8mA     -8.1mA
-945.5mV  -13.94mA   -8.3mA     -17.51mA
-827.3mV  -17.2mA    -12.13mA   -17.46mA
-709.1mV  -16.81mA   -15.79mA   -16.7mA
-590.9mV  -15.78mA   -15.93mA   -15.69mA
-354.6mV  -11.63mA   -11.57mA   -11.82mA
551.5mV   15.66mA    15.15mA    16.51mA
906.1mV   21.65mA    20.73mA    23.3mA
1.261V    23.76mA    22.65mA    25.8mA
1.733V    22.01mA    19.52mA    25.76mA
2.009V    18.19mA    8.04mA     21.28mA
2.364V    5.2mA      2.9mA      15.2mA
[Pullup]
-1.164V   7.3mA      4.062mA    11.85mA
-887.9mV  23.28mA    11.57mA    21.41mA
-730.3mV  24.71mA    20.06mA    22.27mA
-612.1mV  23.69mA    22.22mA    21.84mA
-375.8mV  17.41mA    16.45mA    16.97mA
215.2mV   -7.945mA   -7.529mA   -8.168mA
727.3mV   -18.75mA   -18.09mA   -19.68mA
1.515V    -22.27mA   -20.98mA   -24.11mA
1.791V    -20.55mA   -18.81mA   -23.03mA
1.988V    -19.78mA   -12.79mA   -21.91mA
2.224V    -12mA      -8.343mA   -21.22mA
2.382V    -8.7mA     -7.248mA   -14.29mA
[Ramp]
R_load=50.000Ohm
dV/dt_r   420.489mV/114.000ps  397.005mV/143.500ps  456.867mV/95.500ps
dV/dt_f   420.489mV/125.500ps  396.942mV/162.500ps  456.867mV/106.500ps
[Rising waveform]
R_fixture=50.000Ohm
V_fixture=1.200
V_fixture_min=1.140
V_fixture_max=1.300
0s        511.9mV    487.4mV    541.9mV
52ps      507.1mV    484.3mV    604.8mV
115ps     502.2mV    480.2mV    1.02V
154ps     516mV      478.7mV    1.18V
218ps     702.8mV    488mV      1.268V
269ps     972.1mV    524.3mV    1.288V
320ps     1.115V     637.1mV    1.295V
409ps     1.182V     960mV      1.299V
498ps     1.195V     1.097V     1.3V
1.25ns    1.2V       1.14V      1.3V
[Rising waveform]
R_fixture=50.000Ohm
V_fixture=0
0s        35.33mV    27.47mV    41.33mV
64ps      34.04mV    27.2mV     94.29mV
179ps     35.16mV    20.23mV    590.8mV
230ps     138.9mV    15.69mV    707.3mV
294ps     377.3mV    35.88mV    774.2mV
345ps     533.7mV    107.3mV    797mV
409ps     650.9mV    269.6mV    809.7mV
511ps     721.4mV    520.5mV    817.5mV
613ps     740.5mV    638.3mV    820.1mV
1.25ns    750.3mV    700.6mV    821.1mV
[Falling waveform]
R_fixture=50.000Ohm
V_fixture=1.200
V_fixture_min=1.140
V_fixture_max=1.300
0s        1.2V       1.139V     1.304V
77ps      1.2V       1.139V     1.251V
192ps     1.191V     1.149V     807.4mV
256ps     1.052V     1.153V     659.3mV
320ps     850.5mV    1.113V     596.9mV
383ps     689.5mV    1.004V     571.8mV
447ps     598.9mV    855.2mV    561.2mV
549ps     542.3mV    659.1mV    555mV
639ps     525.8mV    568.9mV    552.9mV
1.25ns    514.2mV    492.4mV    551.2mV
[Falling waveform]
R_fixture=50.000Ohm
V_fixture=0
0s        749.7mV    700.4mV    830.7mV
52ps      753.8mV    703mV      750.1mV
115ps     764.6mV    710.9mV    357.2mV
154ps     744.4mV    715.9mV    193.5mV
230ps     463mV      693.2mV    81.98mV
281ps     228.9mV    604.3mV    62.06mV
332ps     115.4mV    436.2mV    53.76mV
409ps     58.23mV    183.1mV    49.04mV
498ps     41.86mV    69.91mV    47.51mV
1.25ns    34.58mV    26.8mV     47.01mV
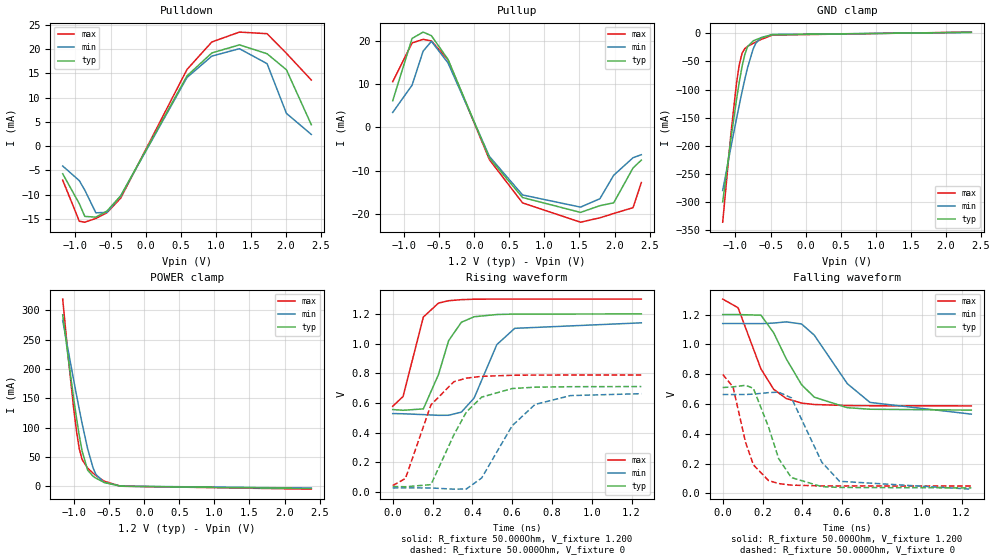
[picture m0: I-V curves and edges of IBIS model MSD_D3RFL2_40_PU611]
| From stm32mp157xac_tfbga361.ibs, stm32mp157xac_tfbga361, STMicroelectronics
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[Model] MSD_D3RFL2_40_PU611
Model_type   I/O
C_comp 2.451pF   2.364pF   2.578pF
Vinh = 820.000mV
Vinl = 380.000mV
Vmeas = 600.000mV
Vref = 600.000mV
[Model Spec]
Vinh   820.000mV   790.000mV   870.000mV
Vinl   380.000mV   350.000mV   430.000mV
Vmeas   600.000mV   570.000mV   650.000mV
Vref   600.000mV   570.000mV   650.000mV
[Temperature Range]   25.000   125.000   -40.000
[Voltage Range]   1.200V   1.140V   1.300V
[GND Clamp Reference]   0.00V   0.00V   0.00V
[Pulldown Reference]   0.00V   0.00V   0.00V
[POWER Clamp Reference]   1.200V   1.140V   1.300V
[Pullup Reference]   1.200V   1.140V   1.300V
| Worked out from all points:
|   slope of the pulldown table from 0 to 0.18 V, typ, clamps not added: 35.6 ohm
|   slope of the pullup table from 0 to 0.18 V, typ, clamps not added: 29.6 ohm
|   GND clamp passes 1 mA (typ) near -0.40 V on its own axis
|   POWER clamp passes 1 mA (typ) near -0.41 V on its own axis
|   rising waveform, R_fixture 50.000Ohm, V_fixture 1.200: 20-80 % time 92.4ps typ, 119ps min, 78.2ps max; typ from 0.556 V to 1.2 V
|   rising waveform, R_fixture 50.000Ohm, V_fixture 0: 20-80 % time 148ps typ, 181ps min, 124ps max; typ from 0.038 V to 0.711 V
|   falling waveform, R_fixture 50.000Ohm, V_fixture 1.200: 20-80 % time 166ps typ, 207ps min, 134ps max; typ from 1.2 V to 0.559 V
|   falling waveform, R_fixture 50.000Ohm, V_fixture 0: 20-80 % time 103ps typ, 128ps min, 86.7ps max; typ from 0.711 V to 0.037 V
[GND Clamp]
-1.182V   -299.4mA   -279.4mA   -335.7mA
-1.064V   -187.2mA   -201.7mA   -177.3mA
-984.9mV  -117.7mA   -151.5mA   -88.45mA
-945.5mV  -86.41mA   -127.2mA   -55.64mA
-906.1mV  -59.01mA   -103.9mA   -35.52mA
-866.7mV  -37.5mA    -81.58mA   -27.1mA
-827.3mV  -23.7mA    -61.03mA   -23.31mA
-748.5mV  -13.53mA   -28.05mA   -17.87mA
-709.1mV  -11.34mA   -17.43mA   -15.36mA
-630.3mV  -7.814mA   -7.472mA   -10.65mA
-472.7mV  -2.424mA   -2.118mA   -3.155mA
2.364V    1.86mA     1.572mA    2.188mA
[Power Clamp]
-1.164V   292.5mA    282.8mA    319.3mA
-1.085V   218.7mA    231.1mA    220.1mA
-1.006V   148.5mA    180.2mA    131.1mA
-966.7mV  116mA      155.3mA    93.34mA
-927.3mV  86.16mA    131mA      63.99mA
-887.9mV  60.42mA    107.5mA    45.87mA
-809.1mV  27.84mA    64.38mA    31.14mA
-730.3mV  17.05mA    31.2mA     22.42mA
-690.9mV  13.96mA    20.37mA    18.55mA
-572.7mV  6.658mA    6.592mA    8.774mA
-336.4mV  200.5uA    379.1uA    223.4uA
2.382V    -3.72mA    -2.96mA    -4.821mA
[Pulldown]
-1.182V   -5.7mA     -4.1mA     -7mA
-945.5mV  -11.84mA   -7.1mA     -15.47mA
-866.7mV  -14.47mA   -9.07mA    -15.66mA
-709.1mV  -14.62mA   -13.73mA   -14.89mA
-551.5mV  -13.37mA   -13.65mA   -13.72mA
-354.6mV  -10.22mA   -10.29mA   -10.7mA
590.9mV   14.46mA    14.13mA    15.78mA
945.5mV   19.18mA    18.53mA    21.44mA
1.339V    20.84mA    20.05mA    23.47mA
1.733V    19.01mA    16.97mA    23.14mA
2.009V    15.71mA    6.74mA     19.1mA
2.364V    4.4mA      2.4mA      13.6mA
[Pullup]
-1.164V   6.1mA      3.409mA    10.52mA
-887.9mV  20.5mA     9.71mA     19.46mA
-730.3mV  21.97mA    17.56mA    20.29mA
-612.1mV  21.14mA    19.84mA    19.93mA
-375.8mV  15.67mA    14.87mA    15.59mA
215.2mV   -7.105mA   -6.743mA   -7.481mA
687.9mV   -16.23mA   -15.64mA   -17.47mA
1.515V    -19.67mA   -18.45mA   -21.93mA
1.791V    -18.12mA   -16.51mA   -20.92mA
1.988V    -17.45mA   -11.09mA   -19.92mA
2.264V    -9.4mA     -7.043mA   -18.57mA
2.382V    -7.6mA     -6.348mA   -12.78mA
[Ramp]
R_load=50.000Ohm
dV/dt_r   394.617mV/121.000ps  373.875mV/151.500ps  435.492mV/101.000ps
dV/dt_f   394.617mV/135.500ps  373.815mV/169.500ps  435.492mV/110.500ps
[Rising waveform]
R_fixture=50.000Ohm
V_fixture=1.200
V_fixture_min=1.140
V_fixture_max=1.300
0s        556.3mV    529.2mV    578.2mV
52ps      551.4mV    527.9mV    644.1mV
154ps     560.8mV    522.3mV    1.179V
230ps     792.3mV    517.4mV    1.273V
281ps     1.02V      517.9mV    1.289V
345ps     1.144V     539mV      1.296V
409ps     1.181V     633.8mV    1.299V
523ps     1.196V     993.3mV    1.3V
613ps     1.199V     1.103V     1.3V
1.249ns   1.2V       1.14V      1.3V
[Rising waveform]
R_fixture=50.000Ohm
V_fixture=0
0s        38.01mV    28.79mV    44.5mV
64ps      36.82mV    29.16mV    92.35mV
192ps     50.81mV    28.59mV    587.6mV
307ps     385.1mV    20.41mV    743.6mV
370ps     539.7mV    21.61mV    767.8mV
447ps     640mV      95.8mV     779.8mV
600ps     697.7mV    447.2mV    787.1mV
715ps     706.7mV    590.7mV    788.5mV
893ps     710.1mV    650.3mV    788.8mV
1.249ns   711.2mV    663.1mV    788.9mV
[Falling waveform]
R_fixture=50.000Ohm
V_fixture=1.200
V_fixture_min=1.140
V_fixture_max=1.300
0s        1.2V       1.14V      1.304V
77ps      1.2V       1.14V      1.246V
192ps     1.196V     1.139V     835.8mV
256ps     1.078V     1.143V     698.8mV
319ps     903.8mV    1.151V     636.9mV
396ps     729.9mV    1.137V     606.3mV
460ps     645.9mV    1.062V     596.7mV
626ps     575.4mV    736.4mV    589.6mV
740ps     564.9mV    610.6mV    588.3mV
1.249ns   558.9mV    532.1mV    587.4mV
[Falling waveform]
R_fixture=50.000Ohm
V_fixture=0
0s        710.7mV    663.8mV    798.3mV
52ps      714.9mV    663.5mV    714.1mV
115ps     725.5mV    664mV      342.2mV
154ps     705.3mV    666.4mV    192.1mV
230ps     446.8mV    676.3mV    86.75mV
281ps     233.8mV    679.6mV    66.08mV
345ps     106.3mV    641.5mV    55.89mV
498ps     45.75mV    209.2mV    50.43mV
587ps     40.23mV    81.52mV    50.06mV
1.249ns   37.32mV    28.75mV    49.86mV
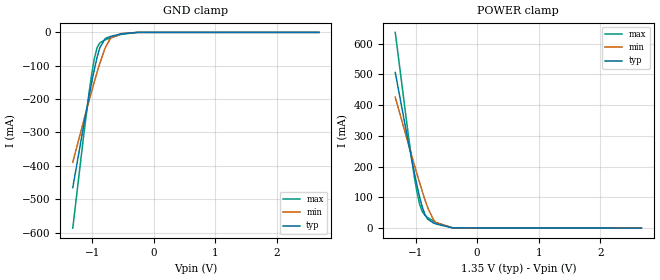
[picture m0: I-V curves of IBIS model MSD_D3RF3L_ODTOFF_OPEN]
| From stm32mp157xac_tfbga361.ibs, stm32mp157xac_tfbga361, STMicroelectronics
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[Model] MSD_D3RF3L_ODTOFF_OPEN
Model_type   Input
C_comp 2.571pF   2.485pF   2.698pF
Vinh = 810.000mV
Vinl = 540.000mV
[Temperature Range]   25.000   125.000   -40.000
[Voltage Range]   1.350V   1.283V   1.450V
[GND Clamp Reference]   0.00V   0.00V   0.00V
[POWER Clamp Reference]   1.350V   1.283V   1.450V
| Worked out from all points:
|   GND clamp passes 1 mA (typ) near -0.40 V on its own axis
|   POWER clamp passes 1 mA (typ) near -0.41 V on its own axis
[GND Clamp]
-1.318V   -465.4mA   -389.6mA   -586.9mA
-1.142V   -280.7mA   -266.2mA   -311.3mA
-1.055V   -192mA     -205.8mA   -182.9mA
-1.011V   -149.8mA   -176.3mA   -125.7mA
-966.7mV  -110.1mA   -147.4mA   -78.04mA
-922.7mV  -74.69mA   -119.4mA   -45.74mA
-878.8mV  -46.1mA    -92.75mA   -31.44mA
-790.9mV  -18.44mA   -46.33mA   -22.58mA
-703mV    -11.89mA   -17.04mA   -16.32mA
-527.3mV  -4.306mA   -3.622mA   -5.804mA
-263.6mV  -40.63uA   -79uA      -28.74uA
2.68V     29.66nA    782.6nA    3.866nA
[Power Clamp]
-1.33V    505.8mA    425.5mA    636.2mA
-1.111V   272.2mA    269mA      291.8mA
-1.023V   182.5mA    207.6mA    169.9mA
-978.8mV  140.4mA    177.5mA    118.4mA
-934.9mV  101.7mA    147.9mA    78.03mA
-890.9mV  68.52mA    119.2mA    53.53mA
-847mV    43.69mA    91.95mA    41.5mA
-803mV    29.03mA    67.01mA    34.38mA
-715.1mV  17.24mA    28.94mA    23.33mA
-671.2mV  13.66mA    17.91mA    18.55mA
-407.6mV  1.002mA    1.3mA      1.222mA
2.668V    -48.51nA   -903.7nA   -4.563nA
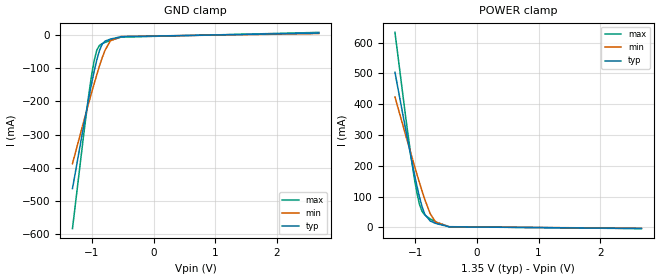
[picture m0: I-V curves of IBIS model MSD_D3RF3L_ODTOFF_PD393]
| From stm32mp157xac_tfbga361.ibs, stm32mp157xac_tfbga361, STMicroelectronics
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[Model] MSD_D3RF3L_ODTOFF_PD393
Model_type   Input
C_comp 2.363pF   2.279pF   2.485pF
Vinh = 810.000mV
Vinl = 540.000mV
[Model Spec]
Vinh   810.000mV   777.000mV   860.000mV
Vinl   540.000mV   507.000mV   590.000mV
[Temperature Range]   25.000   125.000   -40.000
[Voltage Range]   1.350V   1.283V   1.450V
[GND Clamp Reference]   0.00V   0.00V   0.00V
[POWER Clamp Reference]   1.350V   1.283V   1.450V
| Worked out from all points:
|   GND clamp passes 1 mA (typ) near -0.40 V on its own axis
|   POWER clamp passes 1 mA (typ) near -0.41 V on its own axis
[GND Clamp]
-1.318V   -463.4mA   -388mA     -584.4mA
-1.142V   -279.1mA   -264.9mA   -309.4mA
-1.055V   -190.7mA   -204.7mA   -181.2mA
-1.011V   -148.5mA   -175.2mA   -124.1mA
-966.7mV  -109mA     -146.4mA   -76.53mA
-922.7mV  -73.63mA   -118.5mA   -44.35mA
-878.8mV  -45.13mA   -91.96mA   -30.17mA
-834.9mV  -26.53mA   -67.36mA   -24.96mA
-790.9mV  -17.66mA   -45.7mA    -21.55mA
-703mV    -11.29mA   -16.55mA   -15.52mA
-527.3mV  -4.033mA   -3.396mA   -5.438mA
2.68V     6.816mA    5.299mA    8.859mA
[Power Clamp]
-1.33V    503.6mA    423.4mA    633.4mA
-1.155V   316.5mA    298.5mA    356.2mA
-1.067V   225.1mA    236.8mA    226.5mA
-1.023V   181.1mA    206.3mA    168.1mA
-978.8mV  139.1mA    176.2mA    116.8mA
-934.9mV  100.5mA    146.8mA    76.52mA
-890.9mV  67.41mA    118.2mA    52.15mA
-847mV    42.68mA    91.04mA    40.24mA
-759.1mV  20.93mA    44.8mA     27.57mA
-671.2mV  13.07mA    17.35mA    17.81mA
-451.5mV  1.841mA    2.073mA    2.334mA
2.668V    -3.43mA    -2.854mA   -4.086mA
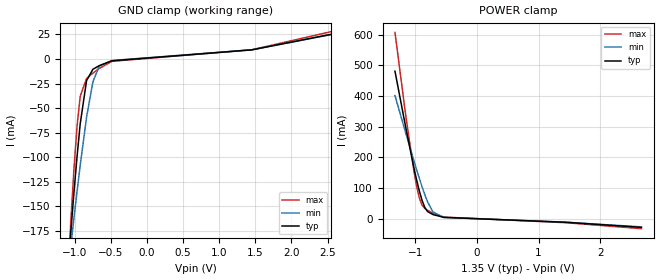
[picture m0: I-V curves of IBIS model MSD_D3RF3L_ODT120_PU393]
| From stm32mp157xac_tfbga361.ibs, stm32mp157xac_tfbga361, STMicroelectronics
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[Model] MSD_D3RF3L_ODT120_PU393
Model_type   Input
C_comp 2.325pF   2.246pF   2.415pF
Vinh = 810.000mV
Vinl = 540.000mV
[Temperature Range]   25.000   125.000   -40.000
[Voltage Range]   1.350V   1.283V   1.450V
[GND Clamp Reference]   0.00V   0.00V   0.00V
[POWER Clamp Reference]   1.350V   1.283V   1.450V
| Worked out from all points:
|   GND clamp passes 1 mA (typ) near -0.43 V on its own axis
|   POWER clamp passes 1 mA (typ) near -0.31 V on its own axis
[GND Clamp]
-1.318V   -446.1mA   -371mA     -564.4mA
-1.098V   -221mA     -220.9mA   -229.3mA
-1.055V   -178.3mA   -191.7mA   -168.7mA
-1.011V   -137.5mA   -163.1mA   -114mA
-966.7mV  -99.54mA   -135.1mA   -68.83mA
-922.7mV  -66.1mA    -108.2mA   -37.98mA
-834.9mV  -22.01mA   -59.31mA   -19.83mA
-747mV    -10.45mA   -23.29mA   -14.35mA
-659.1mV  -6.745mA   -7.235mA   -9.587mA
-483.3mV  -1.802mA   -1.516mA   -2.34mA
1.45V     9.323mA    9.416mA    9.417mA
2.68V     27.04mA    26.74mA    30.07mA
[Power Clamp]
-1.33V    481.3mA    401.8mA    607.8mA
-1.155V   297.6mA    279.3mA    336mA
-1.023V   166.4mA    189.5mA    156mA
-978.8mV  126.7mA    160.4mA    106.7mA
-934.9mV  90.86mA    132mA      67.97mA
-890.9mV  60.33mA    104.7mA    44.79mA
-847mV    37.44mA    79.17mA    33.91mA
-803mV    24.09mA    56.2mA     27.84mA
-715.1mV  14.05mA    22.8mA     18.67mA
-539.4mV  4.861mA    4.567mA    5.756mA
1.438V    -11.13mA   -10.88mA   -12.51mA
2.668V    -27.83mA   -26.21mA   -31.98mA
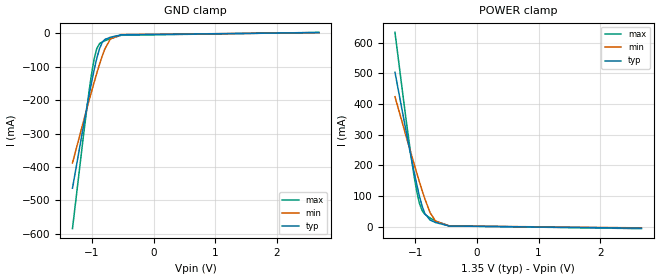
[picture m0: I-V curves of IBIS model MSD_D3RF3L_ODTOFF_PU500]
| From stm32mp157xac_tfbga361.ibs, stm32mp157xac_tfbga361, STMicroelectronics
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[Model] MSD_D3RF3L_ODTOFF_PU500
Model_type   Input
C_comp 2.412pF   2.327pF   2.536pF
Vinh = 810.000mV
Vinl = 540.000mV
[Temperature Range]   25.000   125.000   -40.000
[Voltage Range]   1.350V   1.283V   1.450V
[GND Clamp Reference]   0.00V   0.00V   0.00V
[POWER Clamp Reference]   1.350V   1.283V   1.450V
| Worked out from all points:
|   GND clamp passes 1 mA (typ) near -0.40 V on its own axis
|   POWER clamp passes 1 mA (typ) near -0.41 V on its own axis
[GND Clamp]
-1.318V   -463.7mA   -388.2mA   -584.9mA
-1.142V   -279.4mA   -265.2mA   -309.7mA
-1.055V   -190.9mA   -204.9mA   -181.5mA
-1.011V   -148.7mA   -175.4mA   -124.5mA
-966.7mV  -109.1mA   -146.5mA   -76.83mA
-922.7mV  -73.82mA   -118.6mA   -44.63mA
-878.8mV  -45.3mA    -92.08mA   -30.42mA
-834.9mV  -26.68mA   -67.46mA   -25.18mA
-790.9mV  -17.8mA    -45.78mA   -21.75mA
-703mV    -11.39mA   -16.62mA   -15.68mA
-527.3mV  -4.076mA   -3.422mA   -5.505mA
2.68V     2.665mA    2.261mA    3.159mA
[Power Clamp]
-1.33V    504.1mA    424.1mA    634.1mA
-1.155V   317mA      298.9mA    356.7mA
-1.067V   225.6mA    237.2mA    227mA
-1.023V   181.5mA    206.7mA    168.6mA
-978.8mV  139.4mA    176.6mA    117.2mA
-934.9mV  100.8mA    147.1mA    76.89mA
-890.9mV  67.71mA    118.5mA    52.49mA
-847mV    42.95mA    91.35mA    40.55mA
-759.1mV  21.14mA    45.02mA    27.81mA
-671.2mV  13.23mA    17.53mA    17.99mA
-451.5mV  1.896mA    2.14mA     2.392mA
2.668V    -5.255mA   -4.205mA   -6.77mA
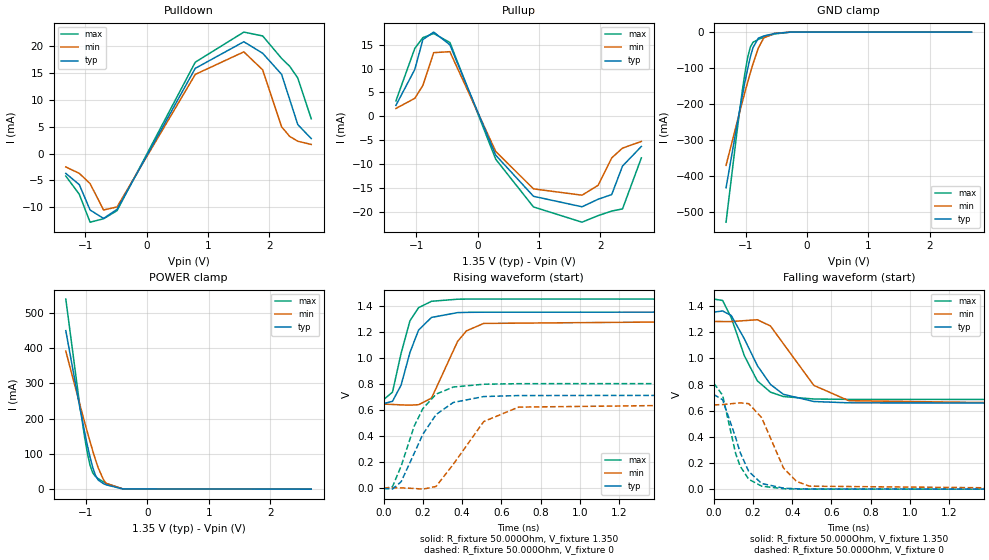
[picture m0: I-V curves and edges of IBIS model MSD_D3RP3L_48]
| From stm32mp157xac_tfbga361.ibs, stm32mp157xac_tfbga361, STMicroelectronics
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[Model] MSD_D3RP3L_48
Model_type   I/O
C_comp 2.240pF   2.158pF   2.357pF
Vinh = 810.000mV
Vinl = 540.000mV
Vmeas = 675.000mV
Vref = 675.000mV
[Model Spec]
Vinh   810.000mV   777.000mV   860.000mV
Vinl   540.000mV   507.000mV   590.000mV
Vmeas   675.000mV   642.000mV   725.000mV
Vref   675.000mV   642.000mV   725.000mV
[Temperature Range]   25.000   125.000   -40.000
[Voltage Range]   1.350V   1.283V   1.450V
[GND Clamp Reference]   0.00V   0.00V   0.00V
[Pulldown Reference]   0.00V   0.00V   0.00V
[POWER Clamp Reference]   1.350V   1.283V   1.450V
[Pullup Reference]   1.350V   1.283V   1.450V
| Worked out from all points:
|   slope of the pulldown table from 0 to 0.203 V, typ, clamps not added: 42.2 ohm
|   slope of the pullup table from 0 to 0.203 V, typ, clamps not added: 34.5 ohm
|   GND clamp passes 1 mA (typ) near -0.41 V on its own axis
|   POWER clamp passes 1 mA (typ) near -0.41 V on its own axis
|   rising waveform, R_fixture 50.000Ohm, V_fixture 1.350: 20-80 % time 88.6ps typ, 114ps min, 76.7ps max; typ from 0.648 V to 1.35 V
|   rising waveform, R_fixture 50.000Ohm, V_fixture 0: 20-80 % time 150ps typ, 182ps min, 128ps max; typ from -0.005 V to 0.711 V
|   falling waveform, R_fixture 50.000Ohm, V_fixture 1.350: 20-80 % time 156ps typ, 190ps min, 125ps max; typ from 1.35 V to 0.658 V
|   falling waveform, R_fixture 50.000Ohm, V_fixture 0: 20-80 % time 99.7ps typ, 118ps min, 83.5ps max; typ from 0.724 V to 0 V
[GND Clamp]
-1.318V   -432mA     -369.8mA   -527.4mA
-1.142V   -260.2mA   -252.4mA   -279.5mA
-1.055V   -177.9mA   -195mA     -164.8mA
-1.011V   -138.8mA   -167mA     -113.9mA
-966.7mV  -102.2mA   -139.6mA   -71.13mA
-922.7mV  -69.41mA   -113.1mA   -41.59mA
-878.8mV  -42.86mA   -87.83mA   -28.26mA
-790.9mV  -16.84mA   -43.84mA   -20.19mA
-703mV    -10.77mA   -15.97mA   -14.59mA
-527.3mV  -3.881mA   -3.286mA   -5.179mA
-263.6mV  -34.33uA   -68.91uA   -22.73uA
2.68V     23.23nA    650.7nA    2.895nA
[Power Clamp]
-1.33V    448.9mA    390.9mA    538.4mA
-1.111V   240.1mA    246mA      248.4mA
-1.023V   161.2mA    189.4mA    146.7mA
-978.8mV  124.3mA    161.6mA    102.6mA
-934.9mV  90.54mA    134.5mA    67.58mA
-890.9mV  61.4mA     108.3mA    46.23mA
-847mV    39.26mA    83.52mA    35.86mA
-803mV    26.02mA    60.85mA    29.84mA
-715.1mV  15.45mA    26.31mA    20.45mA
-671.2mV  12.26mA    16.27mA    16.34mA
-407.6mV  879.8uA    1.157mA    1.067mA
2.668V    -39.9nA    -766.6nA   -3.595nA
[Pulldown]
-1.318V   -3.7mA     -2.5mA     -4.2mA
-1.098V   -5.8mA     -3.7mA     -7.6mA
-922.7mV  -10.53mA   -5.6mA     -12.81mA
-703mV    -12.11mA   -10.53mA   -12.17mA
-483.3mV  -10.41mA   -9.97mA    -10.65mA
790.9mV   15.9mA     14.77mA    17.05mA
1.582V    20.87mA    18.98mA    22.67mA
1.889V    18.72mA    15.62mA    21.95mA
2.197V    14.79mA    5mA        17.76mA
2.329V    10.1mA     3.2mA      16.29mA
2.461V    5.4mA      2.3mA      14.1mA
2.68V     2.8mA      1.7mA      6.5mA
[Pullup]
-1.33V    2.3mA      1.652mA    3.235mA
-1.023V   9.8mA      3.767mA    14.2mA
-890.9mV  16.06mA    6.472mA    16.47mA
-715.1mV  17.63mA    13.33mA    17.33mA
-451.5mV  14.98mA    13.53mA    15.46mA
295.4mV   -8.123mA   -7.328mA   -8.963mA
910.6mV   -16.72mA   -15.17mA   -18.95mA
1.702V    -18.92mA   -16.49mA   -22.14mA
1.965V    -17.33mA   -14.41mA   -20.76mA
2.185V    -16.36mA   -8.69mA    -19.81mA
2.361V    -10.4mA    -6.643mA   -19.36mA
2.668V    -6.3mA     -5.248mA   -8.693mA
[Ramp]
R_load=50.000Ohm
dV/dt_r   421.110mV/120.000ps  384.629mV/147.000ps  469.680mV/102.000ps
dV/dt_f   421.110mV/127.500ps  384.629mV/154.000ps  469.680mV/104.000ps
[Rising waveform]
R_fixture=50.000Ohm
V_fixture=1.350
V_fixture_min=1.283
V_fixture_max=1.450
0s        647.6mV    643.5mV    678.2mV
45ps      664.6mV    640.7mV    735.3mV
89ps      789.6mV    637.4mV    1.034V
134ps     1.04V      635.3mV    1.283V
178ps     1.212V     638.9mV    1.384V
244ps     1.309V     689.5mV    1.433V
377ps     1.346V     1.125V     1.449V
422ps     1.348V     1.206V     1.45V
510ps     1.349V     1.263V     1.45V
2.172ns   1.35V      1.283V     1.45V
[Rising waveform]
R_fixture=50.000Ohm
V_fixture=0
0s        -4.6mV     692.6uV    -4.688mV
45ps      -8.977mV   862.3uV    9.112mV
89ps      47.14mV    300.8uV    166.9mV
156ps     266.2mV    -4.475mV   475.3mV
200ps     412.4mV    -9.749mV   609.1mV
267ps     563.1mV    10.99mV    719.7mV
355ps     656.1mV    181.4mV    774.5mV
510ps     701.4mV    509.5mV    796.1mV
688ps     709.1mV    620.4mV    800.3mV
2.172ns   711.3mV    645.2mV    801.3mV
[Falling waveform]
R_fixture=50.000Ohm
V_fixture=1.350
V_fixture_min=1.283
V_fixture_max=1.450
0s        1.354V     1.283V     1.454V
45ps      1.363V     1.282V     1.443V
89ps      1.328V     1.282V     1.312V
156ps     1.149V     1.289V     1.02V
222ps     945mV      1.296V     828.3mV
289ps     800.9mV    1.248V     742mV
355ps     725.3mV    1.112V     708.3mV
510ps     670.4mV    793.8mV    689.5mV
688ps     660.3mV    676.7mV    686.9mV
2.172ns   657.6mV    646.2mV    685.7mV
[Falling waveform]
R_fixture=50.000Ohm
V_fixture=0
0s        724mV      644.6mV    810mV
45ps      683.9mV    646.9mV    718.6mV
111ps     396.9mV    656.9mV    275.2mV
134ps     282.4mV    660.2mV    177.2mV
178ps     135.6mV    654mV      75.93mV
244ps     43.59mV    547mV      22.92mV
355ps     7.825mV    162.4mV    3.283mV
422ps     2.997mV    59.15mV    996.5uV
488ps     1.168mV    22.87mV    361uV
2.172ns   0V         3.192uV    0V
